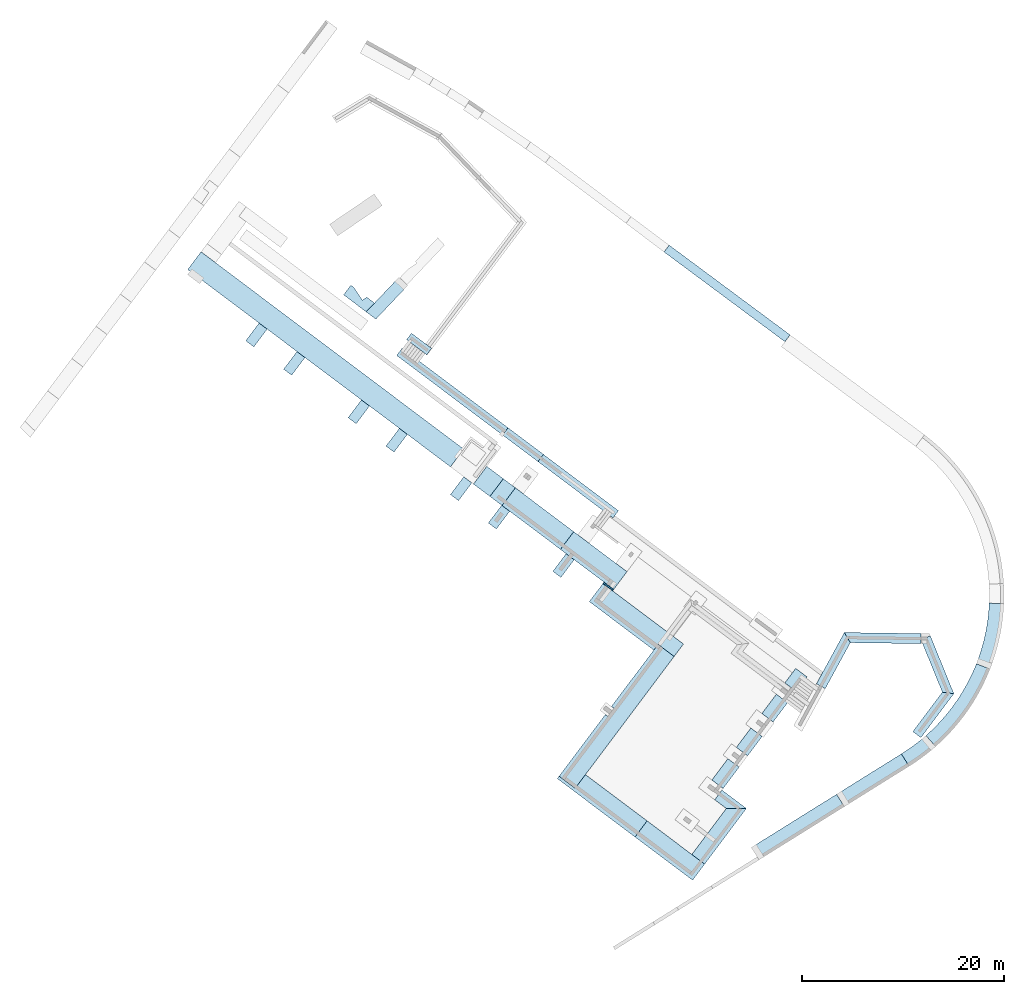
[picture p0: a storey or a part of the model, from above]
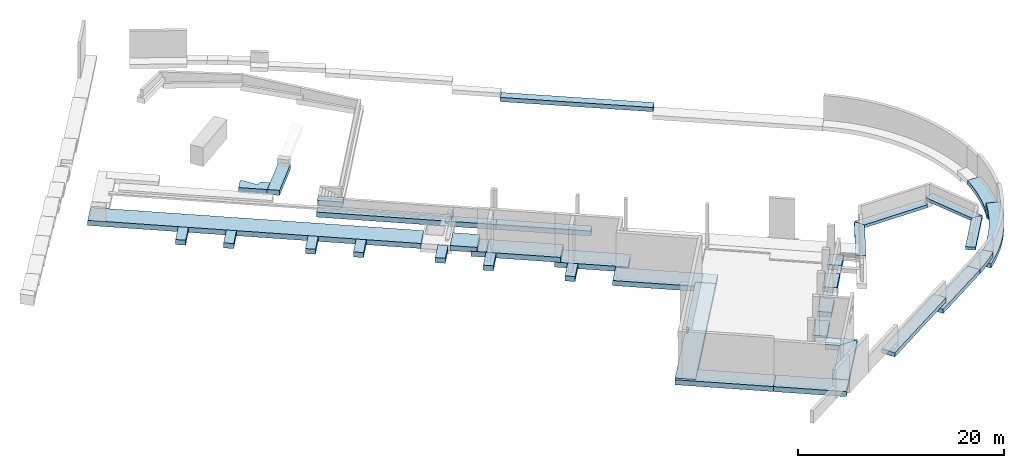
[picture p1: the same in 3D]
Properties of the parts of a building model (IFC2X3), part 1 of 3

# File
Description: ViewDefinition [CoordinationView_V2.0], RevitIdentifiers [VersionGUID: 9e385aeb-7092-4122-8eb9-5f535664c377, NumberOfSaves: 59], CoordinateReference [CoordinateBase: Coordenadas compartidas, ProjectSite: Interna]
File name: 0001
Time: 2024-03-04T15:58:39
Written by: ODA IFC SDK 22.8
Made in: 22.1.50.17 - Exporter 22.6.2.0 - IU alternativa 22.6.2.0

# IfcProject, 0001
LongName: TÍTOL DEL PROJECTE; Phase: Estado de proyecto

# IfcSite, Default
RefLatitude: 40, 24, 0, 5493; RefLongitude: -3, -40, -59, -880065; RefElevation: 0 m

# IfcBuilding
Pset_BuildingCommon - NumberOfStoreys: 4

# IfcBuildingStorey: Nivel:A- Nivell (4)
Name | LongName | Elevation (m)
PS1- Gimnàs | PS1- Gimnàs | -5.45
PS1- Vestuari | PS1- Vestuari | -4.46
P0- Escola | P0- Escola | 0
PC- Coberta STR | PC- Coberta STR | 3.4

# IfcBeam: STR- R- Formigó- Rectangular- T1:40x45 cm (6)
Type - PredefinedType: BEAM; Material: _Formigó- T1- STR
Type - Pset_BeamCommon - IsExternal: no; LoadBearing: yes
Pset_BeamCommon - Slope: 0 deg; Reference: 40x45 cm
Pset_QuantityTakeOff - Reference: 40x45 cm; sets with these values: 2
Name (STR- R- Formigó- Rectangular- T1:40x45 cm:...) | In | Span (m)
41830 | PS1- Vestuari | 2.14
41832 | PS1- Vestuari | 1.68
41862 | PS1- Gimnàs | 2.86
41888 | PS1- Gimnàs | 2.275
41890 | PS1- Vestuari | 0.88
42095 | PS1- Gimnàs | 2.96

# IfcBeam: STR- R- Formigó- Rectangular- T1:40x60 cm (11)
Type - PredefinedType: BEAM; Material: _Formigó- T1- STR
Type - Pset_BeamCommon - IsExternal: no; LoadBearing: yes
Pset_BeamCommon - Slope: 0 deg; Reference: 40x60 cm
Pset_QuantityTakeOff - Reference: 40x60 cm; sets with these values: 2
Name (STR- R- Formigó- Rectangular- T1:40x60 cm:...) | In | Span (m) | Material
41761 | P0- Escola | 58.775
41763 | P0- Escola | 14.275 | _Formigó- T1- STR, _Formigó Pobre- T1- STR
41765 | P0- Escola | 14.275 | _Formigó- T1- STR, _Formigó Pobre- T1- STR
41767 | P0- Escola | 14.275 | _Formigó- T1- STR, _Formigó Pobre- T1- STR
41772 | P0- Escola | 14.527 | _Formigó- T1- STR, _Formigó Pobre- T1- STR
41778 | P0- Escola | 14.527 | _Formigó- T1- STR, _Formigó Pobre- T1- STR
41784 | P0- Escola | 14.527 | _Formigó- T1- STR, _Formigó Pobre- T1- STR
41790 | P0- Escola | 14.527 | _Formigó- T1- STR, _Formigó Pobre- T1- STR
41796 | P0- Escola | 14.527 | _Formigó- T1- STR, _Formigó Pobre- T1- STR
41834 | PS1- Vestuari | 0.6
41860 | PS1- Gimnàs | 3.539

# IfcBeam: STR- V- Acer- FL - Platina- T1:FL 10x190 (2)
In: P0- Escola
Type - Pset_BeamCommon - IsExternal: no; LoadBearing: yes
Material: _Acer- STR; Group: Grupo de modelo:Conjunt Pergola pati infantil:42531
Pset_BeamCommon - Slope: 0 deg; Reference: FL 10x190; Span: 1.3 m
Pset_QuantityTakeOff - Reference: FL 10x190; sets with these values: 2
Name (STR- V- Acer- FL - Platina- T1:FL 10x190:...)
43241
43243

# IfcBeam: STR- V- Acer- FL - Platina- T1:FL 10x200 (3)
In: P0- Escola
Type - Pset_BeamCommon - IsExternal: no; LoadBearing: yes
Material: _Acer- STR
Pset_BeamCommon - Slope: 0 deg; Reference: FL 10x200
Pset_QuantityTakeOff - Reference: FL 10x200; sets with these values: 2
Name (STR- V- Acer- FL - Platina- T1:FL 10x200:...) | Span (m) | Group
43237 | 1.3 | Grupo de modelo:Conjunt Pergola pati infantil:42531
43239 | 1.3 | Grupo de modelo:Conjunt Pergola pati infantil:42531
98464 | 5.349

# IfcBeam: STR- V- Acer- FL - Platina- T1:FL 10x400, STR- V- Acer- FL - Platina- T1:FL 10x400:98261
In: P0- Escola
Type - Pset_BeamCommon - IsExternal: no; LoadBearing: yes
Material: _Acer- STR
Pset_BeamCommon - Slope: 0 deg; Reference: FL 10x400; Span: 1.486 m
Pset_QuantityTakeOff - Reference: FL 10x400; sets with these values: 2

# IfcBeam: STR- V- Acer- FL - Platina- T1:FL 10x80 (4)
In: P0- Escola
Type - Pset_BeamCommon - IsExternal: no; LoadBearing: yes
Material: _Acer- STR
Pset_BeamCommon - Slope: 0 deg; Reference: FL 10x80
Pset_QuantityTakeOff - Reference: FL 10x80; sets with these values: 2
Name (STR- V- Acer- FL - Platina- T1:FL 10x80:...) | Span (m)
104013 | 6.208
104717 | 5.345
105014 | 4.76
105016 | 5.345

# IfcBeam: STR- V- Acer- RHS- Rectangular- T1:120x40RHS - (576)
In: PC- Coberta STR
Type - Pset_BeamCommon - IsExternal: no; LoadBearing: yes
Material: _Acer- STR
Pset_BeamCommon - Slope: 0 deg; Reference: 120x40RHS -
Pset_QuantityTakeOff - Reference: 120x40RHS -; sets with these values: 2
Name (STR- V- Acer- RHS- Rectangular- T1:120x40RHS -:...) | Span (m) | Group
176775 | 1.94 | Grupo de modelo:Grupo de matriz 6:196769
177084 | 2.195 | Grupo de modelo:Grupo de matriz 3:177522
177525 | 2.195 | Grupo de modelo:Grupo de matriz 3:177527
177549 | 2.195 | Grupo de modelo:Grupo de matriz 3:177551
177553 | 2.195 | Grupo de modelo:Grupo de matriz 3:177555
177557 | 2.195 | Grupo de modelo:Grupo de matriz 3:177559
177561 | 2.195 | Grupo de modelo:Grupo de matriz 3:177563
177565 | 2.195 | Grupo de modelo:Grupo de matriz 3:177567
177569 | 2.195 | Grupo de modelo:Grupo de matriz 3:177571
177573 | 2.195 | Grupo de modelo:Grupo de matriz 3:177575
177577 | 2.195 | Grupo de modelo:Grupo de matriz 3:177579
177581 | 2.195 | Grupo de modelo:Grupo de matriz 3:177583
177585 | 2.195 | Grupo de modelo:Grupo de matriz 3:177587
177589 | 2.195 | Grupo de modelo:Grupo de matriz 3:177591
177593 | 2.195 | Grupo de modelo:Grupo de matriz 3:177595
177597 | 2.195 | Grupo de modelo:Grupo de matriz 3:177599
177657 | 2.195 | Grupo de modelo:Grupo de matriz 3:177659
177673 | 2.195 | Grupo de modelo:Grupo de matriz 3:177675
177676 | 2.195 | Grupo de modelo:Grupo de matriz 3:177678
177683 | 2.195 | Grupo de modelo:Grupo de matriz 3:177685
177686 | 2.195 | Grupo de modelo:Grupo de matriz 3:177688
177689 | 2.195 | Grupo de modelo:Grupo de matriz 3:177691
177692 | 2.195 | Grupo de modelo:Grupo de matriz 3:177694
177695 | 2.195 | Grupo de modelo:Grupo de matriz 3:177697
177698 | 2.195 | Grupo de modelo:Grupo de matriz 3:177700
177701 | 2.195 | Grupo de modelo:Grupo de matriz 3:177703
177704 | 2.195 | Grupo de modelo:Grupo de matriz 3:177706
177707 | 2.195 | Grupo de modelo:Grupo de matriz 3:177709
177710 | 2.195 | Grupo de modelo:Grupo de matriz 3:177712
177713 | 2.195 | Grupo de modelo:Grupo de matriz 3:177715
177716 | 2.195 | Grupo de modelo:Grupo de matriz 3:177718
177719 | 2.195 | Grupo de modelo:Grupo de matriz 3:177721
177722 | 2.195 | Grupo de modelo:Grupo de matriz 3:177724
178431 | 1.94 | Grupo de modelo:Grupo de matriz 5:187539
181486 | 2.195 | Grupo de modelo:Grupo de matriz 3:181538
181539 | 2.195 | Grupo de modelo:Grupo de matriz 3:181541
181546 | 2.195 | Grupo de modelo:Grupo de matriz 3:181548
181549 | 2.195 | Grupo de modelo:Grupo de matriz 3:181551
181552 | 2.195 | Grupo de modelo:Grupo de matriz 3:181554
181555 | 2.195 | Grupo de modelo:Grupo de matriz 3:181557
181558 | 2.195 | Grupo de modelo:Grupo de matriz 3:181560
181561 | 2.195 | Grupo de modelo:Grupo de matriz 3:181563
181564 | 2.195 | Grupo de modelo:Grupo de matriz 3:181566
181567 | 2.195 | Grupo de modelo:Grupo de matriz 3:181569
181570 | 2.195 | Grupo de modelo:Grupo de matriz 3:181572
181573 | 2.195 | Grupo de modelo:Grupo de matriz 3:181575
181576 | 2.195 | Grupo de modelo:Grupo de matriz 3:181578
181579 | 2.195 | Grupo de modelo:Grupo de matriz 3:181581
181582 | 2.195 | Grupo de modelo:Grupo de matriz 3:181584
181585 | 2.195 | Grupo de modelo:Grupo de matriz 3:181587
181589 | 2.195 | Grupo de modelo:Grupo de matriz 3:181591
181592 | 2.195 | Grupo de modelo:Grupo de matriz 3:181594
181599 | 2.195 | Grupo de modelo:Grupo de matriz 3:181601
181602 | 2.195 | Grupo de modelo:Grupo de matriz 3:181604
181605 | 2.195 | Grupo de modelo:Grupo de matriz 3:181607
181608 | 2.195 | Grupo de modelo:Grupo de matriz 3:181610
181611 | 2.195 | Grupo de modelo:Grupo de matriz 3:181613
181614 | 2.195 | Grupo de modelo:Grupo de matriz 3:181616
181617 | 2.195 | Grupo de modelo:Grupo de matriz 3:181619
181620 | 2.195 | Grupo de modelo:Grupo de matriz 3:181622
181623 | 2.195 | Grupo de modelo:Grupo de matriz 3:181625
181626 | 2.195 | Grupo de modelo:Grupo de matriz 3:181628
181629 | 2.195 | Grupo de modelo:Grupo de matriz 3:181631
181632 | 2.195 | Grupo de modelo:Grupo de matriz 3:181634
181635 | 2.195 | Grupo de modelo:Grupo de matriz 3:181637
181638 | 2.195 | Grupo de modelo:Grupo de matriz 3:181640
181968 | 2.195 | Grupo de modelo:Grupo de matriz 3:182020
182021 | 2.195 | Grupo de modelo:Grupo de matriz 3:182023
182028 | 2.195 | Grupo de modelo:Grupo de matriz 3:182030
182031 | 2.195 | Grupo de modelo:Grupo de matriz 3:182033
182034 | 2.195 | Grupo de modelo:Grupo de matriz 3:182036
182037 | 2.195 | Grupo de modelo:Grupo de matriz 3:182039
182040 | 2.195 | Grupo de modelo:Grupo de matriz 3:182042
182043 | 2.195 | Grupo de modelo:Grupo de matriz 3:182045
182046 | 2.195 | Grupo de modelo:Grupo de matriz 3:182048
182049 | 2.195 | Grupo de modelo:Grupo de matriz 3:182051
182052 | 2.195 | Grupo de modelo:Grupo de matriz 3:182054
182055 | 2.195 | Grupo de modelo:Grupo de matriz 3:182057
182058 | 2.195 | Grupo de modelo:Grupo de matriz 3:182060
182061 | 2.195 | Grupo de modelo:Grupo de matriz 3:182063
182064 | 2.195 | Grupo de modelo:Grupo de matriz 3:182066
182067 | 2.195 | Grupo de modelo:Grupo de matriz 3:182069
182071 | 2.195 | Grupo de modelo:Grupo de matriz 3:182073
182074 | 2.195 | Grupo de modelo:Grupo de matriz 3:182076
182081 | 2.195 | Grupo de modelo:Grupo de matriz 3:182083
182084 | 2.195 | Grupo de modelo:Grupo de matriz 3:182086
182087 | 2.195 | Grupo de modelo:Grupo de matriz 3:182089
182090 | 2.195 | Grupo de modelo:Grupo de matriz 3:182092
182093 | 2.195 | Grupo de modelo:Grupo de matriz 3:182095
182096 | 2.195 | Grupo de modelo:Grupo de matriz 3:182098
182099 | 2.195 | Grupo de modelo:Grupo de matriz 3:182101
182102 | 2.195 | Grupo de modelo:Grupo de matriz 3:182104
182105 | 2.195 | Grupo de modelo:Grupo de matriz 3:182107
182108 | 2.195 | Grupo de modelo:Grupo de matriz 3:182110
182111 | 2.195 | Grupo de modelo:Grupo de matriz 3:182113
182114 | 2.195 | Grupo de modelo:Grupo de matriz 3:182116
182117 | 2.195 | Grupo de modelo:Grupo de matriz 3:182119
182120 | 2.195 | Grupo de modelo:Grupo de matriz 3:182122
182450 | 2.195 | Grupo de modelo:Grupo de matriz 3:182502
182503 | 2.195 | Grupo de modelo:Grupo de matriz 3:182505
182510 | 2.195 | Grupo de modelo:Grupo de matriz 3:182512
182513 | 2.195 | Grupo de modelo:Grupo de matriz 3:182515
182516 | 2.195 | Grupo de modelo:Grupo de matriz 3:182518
182519 | 2.195 | Grupo de modelo:Grupo de matriz 3:182521
182522 | 2.195 | Grupo de modelo:Grupo de matriz 3:182524
182525 | 2.195 | Grupo de modelo:Grupo de matriz 3:182527
182528 | 2.195 | Grupo de modelo:Grupo de matriz 3:182530
182531 | 2.195 | Grupo de modelo:Grupo de matriz 3:182533
182534 | 2.195 | Grupo de modelo:Grupo de matriz 3:182536
182537 | 2.195 | Grupo de modelo:Grupo de matriz 3:182539
182540 | 2.195 | Grupo de modelo:Grupo de matriz 3:182542
182543 | 2.195 | Grupo de modelo:Grupo de matriz 3:182545
182546 | 2.195 | Grupo de modelo:Grupo de matriz 3:182548
182549 | 2.195 | Grupo de modelo:Grupo de matriz 3:182551
182553 | 2.195 | Grupo de modelo:Grupo de matriz 3:182555
182556 | 2.195 | Grupo de modelo:Grupo de matriz 3:182558
182563 | 2.195 | Grupo de modelo:Grupo de matriz 3:182565
182566 | 2.195 | Grupo de modelo:Grupo de matriz 3:182568
182569 | 2.195 | Grupo de modelo:Grupo de matriz 3:182571
182572 | 2.195 | Grupo de modelo:Grupo de matriz 3:182574
182575 | 2.195 | Grupo de modelo:Grupo de matriz 3:182577
182578 | 2.195 | Grupo de modelo:Grupo de matriz 3:182580
182581 | 2.195 | Grupo de modelo:Grupo de matriz 3:182583
182584 | 2.195 | Grupo de modelo:Grupo de matriz 3:182586
182587 | 2.195 | Grupo de modelo:Grupo de matriz 3:182589
182590 | 2.195 | Grupo de modelo:Grupo de matriz 3:182592
182593 | 2.195 | Grupo de modelo:Grupo de matriz 3:182595
182596 | 2.195 | Grupo de modelo:Grupo de matriz 3:182598
182599 | 2.195 | Grupo de modelo:Grupo de matriz 3:182601
182602 | 2.195 | Grupo de modelo:Grupo de matriz 3:182604
187542 | 1.94 | Grupo de modelo:Grupo de matriz 5:187544
187568 | 1.94 | Grupo de modelo:Grupo de matriz 5:187570
187572 | 1.94 | Grupo de modelo:Grupo de matriz 5:187574
187576 | 1.94 | Grupo de modelo:Grupo de matriz 5:187578
187580 | 1.94 | Grupo de modelo:Grupo de matriz 5:187582
187584 | 1.94 | Grupo de modelo:Grupo de matriz 5:187586
187588 | 1.94 | Grupo de modelo:Grupo de matriz 5:187590
187592 | 1.94 | Grupo de modelo:Grupo de matriz 5:187594
187596 | 1.94 | Grupo de modelo:Grupo de matriz 5:187598
187600 | 1.94 | Grupo de modelo:Grupo de matriz 5:187602
187604 | 1.94 | Grupo de modelo:Grupo de matriz 5:187606
187608 | 1.94 | Grupo de modelo:Grupo de matriz 5:187610
187612 | 1.94 | Grupo de modelo:Grupo de matriz 5:187614
187616 | 1.94 | Grupo de modelo:Grupo de matriz 5:187618
187677 | 1.94 | Grupo de modelo:Grupo de matriz 5:187679
190967 | 2.195 | Grupo de modelo:Grupo de matriz 3:190969
190970 | 2.195 | Grupo de modelo:Grupo de matriz 3:190972
190977 | 2.195 | Grupo de modelo:Grupo de matriz 3:190979
190980 | 2.195 | Grupo de modelo:Grupo de matriz 3:190982
190983 | 2.195 | Grupo de modelo:Grupo de matriz 3:190985
190986 | 2.195 | Grupo de modelo:Grupo de matriz 3:190988
190989 | 2.195 | Grupo de modelo:Grupo de matriz 3:190991
190992 | 2.195 | Grupo de modelo:Grupo de matriz 3:190994
190995 | 2.195 | Grupo de modelo:Grupo de matriz 3:190997
190998 | 2.195 | Grupo de modelo:Grupo de matriz 3:191000
191001 | 2.195 | Grupo de modelo:Grupo de matriz 3:191003
191004 | 2.195 | Grupo de modelo:Grupo de matriz 3:191006
191007 | 2.195 | Grupo de modelo:Grupo de matriz 3:191009
191010 | 2.195 | Grupo de modelo:Grupo de matriz 3:191012
191013 | 2.195 | Grupo de modelo:Grupo de matriz 3:191015
191016 | 2.195 | Grupo de modelo:Grupo de matriz 3:191018
191020 | 2.195 | Grupo de modelo:Grupo de matriz 3:191022
191023 | 2.195 | Grupo de modelo:Grupo de matriz 3:191025
191030 | 2.195 | Grupo de modelo:Grupo de matriz 3:191032
191033 | 2.195 | Grupo de modelo:Grupo de matriz 3:191035
191036 | 2.195 | Grupo de modelo:Grupo de matriz 3:191038
191039 | 2.195 | Grupo de modelo:Grupo de matriz 3:191041
191042 | 2.195 | Grupo de modelo:Grupo de matriz 3:191044
191045 | 2.195 | Grupo de modelo:Grupo de matriz 3:191047
191048 | 2.195 | Grupo de modelo:Grupo de matriz 3:191050
191051 | 2.195 | Grupo de modelo:Grupo de matriz 3:191053
191054 | 2.195 | Grupo de modelo:Grupo de matriz 3:191056
191057 | 2.195 | Grupo de modelo:Grupo de matriz 3:191059
191060 | 2.195 | Grupo de modelo:Grupo de matriz 3:191062
191063 | 2.195 | Grupo de modelo:Grupo de matriz 3:191065
191066 | 2.195 | Grupo de modelo:Grupo de matriz 3:191068
191069 | 2.195 | Grupo de modelo:Grupo de matriz 3:191071
191073 | 2.195 | Grupo de modelo:Grupo de matriz 3:191075
191076 | 2.195 | Grupo de modelo:Grupo de matriz 3:191078
191083 | 2.195 | Grupo de modelo:Grupo de matriz 3:191085
191086 | 2.195 | Grupo de modelo:Grupo de matriz 3:191088
191089 | 2.195 | Grupo de modelo:Grupo de matriz 3:191091
191092 | 2.195 | Grupo de modelo:Grupo de matriz 3:191094
191095 | 2.195 | Grupo de modelo:Grupo de matriz 3:191097
191098 | 2.195 | Grupo de modelo:Grupo de matriz 3:191100
191101 | 2.195 | Grupo de modelo:Grupo de matriz 3:191103
191104 | 2.195 | Grupo de modelo:Grupo de matriz 3:191106
191107 | 2.195 | Grupo de modelo:Grupo de matriz 3:191109
191110 | 2.195 | Grupo de modelo:Grupo de matriz 3:191112
191113 | 2.195 | Grupo de modelo:Grupo de matriz 3:191115
191116 | 2.195 | Grupo de modelo:Grupo de matriz 3:191118
191119 | 2.195 | Grupo de modelo:Grupo de matriz 3:191121
191122 | 2.195 | Grupo de modelo:Grupo de matriz 3:191124
191126 | 2.195 | Grupo de modelo:Grupo de matriz 3:191128
191129 | 2.195 | Grupo de modelo:Grupo de matriz 3:191131
191136 | 2.195 | Grupo de modelo:Grupo de matriz 3:191138
191139 | 2.195 | Grupo de modelo:Grupo de matriz 3:191141
191142 | 2.195 | Grupo de modelo:Grupo de matriz 3:191144
191145 | 2.195 | Grupo de modelo:Grupo de matriz 3:191147
191148 | 2.195 | Grupo de modelo:Grupo de matriz 3:191150
191151 | 2.195 | Grupo de modelo:Grupo de matriz 3:191153
191154 | 2.195 | Grupo de modelo:Grupo de matriz 3:191156
191157 | 2.195 | Grupo de modelo:Grupo de matriz 3:191159
191160 | 2.195 | Grupo de modelo:Grupo de matriz 3:191162
191163 | 2.195 | Grupo de modelo:Grupo de matriz 3:191165
191166 | 2.195 | Grupo de modelo:Grupo de matriz 3:191168
191169 | 2.195 | Grupo de modelo:Grupo de matriz 3:191171
191172 | 2.195 | Grupo de modelo:Grupo de matriz 3:191174
191175 | 2.195 | Grupo de modelo:Grupo de matriz 3:191177
191179 | 2.195 | Grupo de modelo:Grupo de matriz 3:191181
191182 | 2.195 | Grupo de modelo:Grupo de matriz 3:191184
191189 | 2.195 | Grupo de modelo:Grupo de matriz 3:191191
191192 | 2.195 | Grupo de modelo:Grupo de matriz 3:191194
191195 | 2.195 | Grupo de modelo:Grupo de matriz 3:191197
191198 | 2.195 | Grupo de modelo:Grupo de matriz 3:191200
191201 | 2.195 | Grupo de modelo:Grupo de matriz 3:191203
191204 | 2.195 | Grupo de modelo:Grupo de matriz 3:191206
191207 | 2.195 | Grupo de modelo:Grupo de matriz 3:191209
191210 | 2.195 | Grupo de modelo:Grupo de matriz 3:191212
191213 | 2.195 | Grupo de modelo:Grupo de matriz 3:191215
191216 | 2.195 | Grupo de modelo:Grupo de matriz 3:191218
191219 | 2.195 | Grupo de modelo:Grupo de matriz 3:191221
191222 | 2.195 | Grupo de modelo:Grupo de matriz 3:191224
191225 | 2.195 | Grupo de modelo:Grupo de matriz 3:191227
191228 | 2.195 | Grupo de modelo:Grupo de matriz 3:191230
194025 | 1.94 | Grupo de modelo:Grupo de matriz 5:194027
194028 | 1.94 | Grupo de modelo:Grupo de matriz 5:194030
194035 | 1.94 | Grupo de modelo:Grupo de matriz 5:194037
194038 | 1.94 | Grupo de modelo:Grupo de matriz 5:194040
194041 | 1.94 | Grupo de modelo:Grupo de matriz 5:194043
194044 | 1.94 | Grupo de modelo:Grupo de matriz 5:194046
194047 | 1.94 | Grupo de modelo:Grupo de matriz 5:194049
194050 | 1.94 | Grupo de modelo:Grupo de matriz 5:194052
194053 | 1.94 | Grupo de modelo:Grupo de matriz 5:194055
194056 | 1.94 | Grupo de modelo:Grupo de matriz 5:194058
194059 | 1.94 | Grupo de modelo:Grupo de matriz 5:194061
194062 | 1.94 | Grupo de modelo:Grupo de matriz 5:194064
194065 | 1.94 | Grupo de modelo:Grupo de matriz 5:194067
194068 | 1.94 | Grupo de modelo:Grupo de matriz 5:194070
194071 | 1.94 | Grupo de modelo:Grupo de matriz 5:194073
194074 | 1.94 | Grupo de modelo:Grupo de matriz 5:194076
194077 | 2.195 | Grupo de modelo:Grupo de matriz 3:194079
194080 | 2.195 | Grupo de modelo:Grupo de matriz 3:194082
194087 | 2.195 | Grupo de modelo:Grupo de matriz 3:194089
194090 | 2.195 | Grupo de modelo:Grupo de matriz 3:194092
194093 | 2.195 | Grupo de modelo:Grupo de matriz 3:194095
194096 | 2.195 | Grupo de modelo:Grupo de matriz 3:194098
194099 | 2.195 | Grupo de modelo:Grupo de matriz 3:194101
194102 | 2.195 | Grupo de modelo:Grupo de matriz 3:194104
194105 | 2.195 | Grupo de modelo:Grupo de matriz 3:194107
194108 | 2.195 | Grupo de modelo:Grupo de matriz 3:194110
194111 | 2.195 | Grupo de modelo:Grupo de matriz 3:194113
194114 | 2.195 | Grupo de modelo:Grupo de matriz 3:194116
194117 | 2.195 | Grupo de modelo:Grupo de matriz 3:194119
194120 | 2.195 | Grupo de modelo:Grupo de matriz 3:194122
194123 | 2.195 | Grupo de modelo:Grupo de matriz 3:194125
194126 | 2.195 | Grupo de modelo:Grupo de matriz 3:194128
194130 | 2.195 | Grupo de modelo:Grupo de matriz 3:194132
194133 | 2.195 | Grupo de modelo:Grupo de matriz 3:194135
194140 | 2.195 | Grupo de modelo:Grupo de matriz 3:194142
194143 | 2.195 | Grupo de modelo:Grupo de matriz 3:194145
194146 | 2.195 | Grupo de modelo:Grupo de matriz 3:194148
194149 | 2.195 | Grupo de modelo:Grupo de matriz 3:194151
194152 | 2.195 | Grupo de modelo:Grupo de matriz 3:194154
194155 | 2.195 | Grupo de modelo:Grupo de matriz 3:194157
194158 | 2.195 | Grupo de modelo:Grupo de matriz 3:194160
194161 | 2.195 | Grupo de modelo:Grupo de matriz 3:194163
194164 | 2.195 | Grupo de modelo:Grupo de matriz 3:194166
194167 | 2.195 | Grupo de modelo:Grupo de matriz 3:194169
194170 | 2.195 | Grupo de modelo:Grupo de matriz 3:194172
194173 | 2.195 | Grupo de modelo:Grupo de matriz 3:194175
194176 | 2.195 | Grupo de modelo:Grupo de matriz 3:194178
194179 | 2.195 | Grupo de modelo:Grupo de matriz 3:194181
194183 | 2.195 | Grupo de modelo:Grupo de matriz 3:194185
194186 | 2.195 | Grupo de modelo:Grupo de matriz 3:194188
194193 | 2.195 | Grupo de modelo:Grupo de matriz 3:194195
194196 | 2.195 | Grupo de modelo:Grupo de matriz 3:194198
194199 | 2.195 | Grupo de modelo:Grupo de matriz 3:194201
194202 | 2.195 | Grupo de modelo:Grupo de matriz 3:194204
194205 | 2.195 | Grupo de modelo:Grupo de matriz 3:194207
194208 | 2.195 | Grupo de modelo:Grupo de matriz 3:194210
194211 | 2.195 | Grupo de modelo:Grupo de matriz 3:194213
194214 | 2.195 | Grupo de modelo:Grupo de matriz 3:194216
194217 | 2.195 | Grupo de modelo:Grupo de matriz 3:194219
194220 | 2.195 | Grupo de modelo:Grupo de matriz 3:194222
194223 | 2.195 | Grupo de modelo:Grupo de matriz 3:194225
194226 | 2.195 | Grupo de modelo:Grupo de matriz 3:194228
194229 | 2.195 | Grupo de modelo:Grupo de matriz 3:194231
194232 | 2.195 | Grupo de modelo:Grupo de matriz 3:194234
194236 | 2.195 | Grupo de modelo:Grupo de matriz 3:194238
194239 | 2.195 | Grupo de modelo:Grupo de matriz 3:194241
194246 | 2.195 | Grupo de modelo:Grupo de matriz 3:194248
194249 | 2.195 | Grupo de modelo:Grupo de matriz 3:194251
194252 | 2.195 | Grupo de modelo:Grupo de matriz 3:194254
194255 | 2.195 | Grupo de modelo:Grupo de matriz 3:194257
194258 | 2.195 | Grupo de modelo:Grupo de matriz 3:194260
194261 | 2.195 | Grupo de modelo:Grupo de matriz 3:194263
194264 | 2.195 | Grupo de modelo:Grupo de matriz 3:194266
194267 | 2.195 | Grupo de modelo:Grupo de matriz 3:194269
194270 | 2.195 | Grupo de modelo:Grupo de matriz 3:194272
194273 | 2.195 | Grupo de modelo:Grupo de matriz 3:194275
194276 | 2.195 | Grupo de modelo:Grupo de matriz 3:194278
194279 | 2.195 | Grupo de modelo:Grupo de matriz 3:194281
194282 | 2.195 | Grupo de modelo:Grupo de matriz 3:194284
194285 | 2.195 | Grupo de modelo:Grupo de matriz 3:194287
194289 | 2.195 | Grupo de modelo:Grupo de matriz 3:194291
194292 | 2.195 | Grupo de modelo:Grupo de matriz 3:194294
194299 | 2.195 | Grupo de modelo:Grupo de matriz 3:194301
194302 | 2.195 | Grupo de modelo:Grupo de matriz 3:194304
194305 | 2.195 | Grupo de modelo:Grupo de matriz 3:194307
194308 | 2.195 | Grupo de modelo:Grupo de matriz 3:194310
194311 | 2.195 | Grupo de modelo:Grupo de matriz 3:194313
194314 | 2.195 | Grupo de modelo:Grupo de matriz 3:194316
194317 | 2.195 | Grupo de modelo:Grupo de matriz 3:194319
194320 | 2.195 | Grupo de modelo:Grupo de matriz 3:194322
194323 | 2.195 | Grupo de modelo:Grupo de matriz 3:194325
194326 | 2.195 | Grupo de modelo:Grupo de matriz 3:194328
194329 | 2.195 | Grupo de modelo:Grupo de matriz 3:194331
194332 | 2.195 | Grupo de modelo:Grupo de matriz 3:194334
194335 | 2.195 | Grupo de modelo:Grupo de matriz 3:194337
194338 | 2.195 | Grupo de modelo:Grupo de matriz 3:194340
194344 | 1.94 | Grupo de modelo:Grupo de matriz 5:194346
194347 | 1.94 | Grupo de modelo:Grupo de matriz 5:194349
194354 | 1.94 | Grupo de modelo:Grupo de matriz 5:194356
194357 | 1.94 | Grupo de modelo:Grupo de matriz 5:194359
194360 | 1.94 | Grupo de modelo:Grupo de matriz 5:194362
194363 | 1.94 | Grupo de modelo:Grupo de matriz 5:194365
194366 | 1.94 | Grupo de modelo:Grupo de matriz 5:194368
194369 | 1.94 | Grupo de modelo:Grupo de matriz 5:194371
194372 | 1.94 | Grupo de modelo:Grupo de matriz 5:194374
194375 | 1.94 | Grupo de modelo:Grupo de matriz 5:194377
194378 | 1.94 | Grupo de modelo:Grupo de matriz 5:194380
194381 | 1.94 | Grupo de modelo:Grupo de matriz 5:194383
194384 | 1.94 | Grupo de modelo:Grupo de matriz 5:194386
194387 | 1.94 | Grupo de modelo:Grupo de matriz 5:194389
194390 | 1.94 | Grupo de modelo:Grupo de matriz 5:194392
194393 | 1.94 | Grupo de modelo:Grupo de matriz 5:194395
194396 | 2.195 | Grupo de modelo:Grupo de matriz 3:194398
194399 | 2.195 | Grupo de modelo:Grupo de matriz 3:194401
194406 | 2.195 | Grupo de modelo:Grupo de matriz 3:194408
194409 | 2.195 | Grupo de modelo:Grupo de matriz 3:194411
194412 | 2.195 | Grupo de modelo:Grupo de matriz 3:194414
194415 | 2.195 | Grupo de modelo:Grupo de matriz 3:194417
194418 | 2.195 | Grupo de modelo:Grupo de matriz 3:194420
194421 | 2.195 | Grupo de modelo:Grupo de matriz 3:194423
194424 | 2.195 | Grupo de modelo:Grupo de matriz 3:194426
194427 | 2.195 | Grupo de modelo:Grupo de matriz 3:194429
194430 | 2.195 | Grupo de modelo:Grupo de matriz 3:194432
194433 | 2.195 | Grupo de modelo:Grupo de matriz 3:194435
194436 | 2.195 | Grupo de modelo:Grupo de matriz 3:194438
194439 | 2.195 | Grupo de modelo:Grupo de matriz 3:194441
194442 | 2.195 | Grupo de modelo:Grupo de matriz 3:194444
194445 | 2.195 | Grupo de modelo:Grupo de matriz 3:194447
194449 | 2.195 | Grupo de modelo:Grupo de matriz 3:194451
194452 | 2.195 | Grupo de modelo:Grupo de matriz 3:194454
194459 | 2.195 | Grupo de modelo:Grupo de matriz 3:194461
194462 | 2.195 | Grupo de modelo:Grupo de matriz 3:194464
194465 | 2.195 | Grupo de modelo:Grupo de matriz 3:194467
194468 | 2.195 | Grupo de modelo:Grupo de matriz 3:194470
194471 | 2.195 | Grupo de modelo:Grupo de matriz 3:194473
194474 | 2.195 | Grupo de modelo:Grupo de matriz 3:194476
194477 | 2.195 | Grupo de modelo:Grupo de matriz 3:194479
194480 | 2.195 | Grupo de modelo:Grupo de matriz 3:194482
194483 | 2.195 | Grupo de modelo:Grupo de matriz 3:194485
194486 | 2.195 | Grupo de modelo:Grupo de matriz 3:194488
194489 | 2.195 | Grupo de modelo:Grupo de matriz 3:194491
194492 | 2.195 | Grupo de modelo:Grupo de matriz 3:194494
194495 | 2.195 | Grupo de modelo:Grupo de matriz 3:194497
194498 | 2.195 | Grupo de modelo:Grupo de matriz 3:194500
194502 | 2.195 | Grupo de modelo:Grupo de matriz 3:194504
194505 | 2.195 | Grupo de modelo:Grupo de matriz 3:194507
194512 | 2.195 | Grupo de modelo:Grupo de matriz 3:194514
194515 | 2.195 | Grupo de modelo:Grupo de matriz 3:194517
194518 | 2.195 | Grupo de modelo:Grupo de matriz 3:194520
194521 | 2.195 | Grupo de modelo:Grupo de matriz 3:194523
194524 | 2.195 | Grupo de modelo:Grupo de matriz 3:194526
194527 | 2.195 | Grupo de modelo:Grupo de matriz 3:194529
194530 | 2.195 | Grupo de modelo:Grupo de matriz 3:194532
194533 | 2.195 | Grupo de modelo:Grupo de matriz 3:194535
194536 | 2.195 | Grupo de modelo:Grupo de matriz 3:194538
194539 | 2.195 | Grupo de modelo:Grupo de matriz 3:194541
194542 | 2.195 | Grupo de modelo:Grupo de matriz 3:194544
194545 | 2.195 | Grupo de modelo:Grupo de matriz 3:194547
194548 | 2.195 | Grupo de modelo:Grupo de matriz 3:194550
194551 | 2.195 | Grupo de modelo:Grupo de matriz 3:194553
194555 | 2.195 | Grupo de modelo:Grupo de matriz 3:194557
194558 | 2.195 | Grupo de modelo:Grupo de matriz 3:194560
194565 | 2.195 | Grupo de modelo:Grupo de matriz 3:194567
194568 | 2.195 | Grupo de modelo:Grupo de matriz 3:194570
194571 | 2.195 | Grupo de modelo:Grupo de matriz 3:194573
194574 | 2.195 | Grupo de modelo:Grupo de matriz 3:194576
194577 | 2.195 | Grupo de modelo:Grupo de matriz 3:194579
194580 | 2.195 | Grupo de modelo:Grupo de matriz 3:194582
194583 | 2.195 | Grupo de modelo:Grupo de matriz 3:194585
194586 | 2.195 | Grupo de modelo:Grupo de matriz 3:194588
194589 | 2.195 | Grupo de modelo:Grupo de matriz 3:194591
194592 | 2.195 | Grupo de modelo:Grupo de matriz 3:194594
194595 | 2.195 | Grupo de modelo:Grupo de matriz 3:194597
194598 | 2.195 | Grupo de modelo:Grupo de matriz 3:194600
194601 | 2.195 | Grupo de modelo:Grupo de matriz 3:194603
194604 | 2.195 | Grupo de modelo:Grupo de matriz 3:194606
194608 | 2.195 | Grupo de modelo:Grupo de matriz 3:194610
194611 | 2.195 | Grupo de modelo:Grupo de matriz 3:194613
194618 | 2.195 | Grupo de modelo:Grupo de matriz 3:194620
194621 | 2.195 | Grupo de modelo:Grupo de matriz 3:194623
194624 | 2.195 | Grupo de modelo:Grupo de matriz 3:194626
194627 | 2.195 | Grupo de modelo:Grupo de matriz 3:194629
194630 | 2.195 | Grupo de modelo:Grupo de matriz 3:194632
194633 | 2.195 | Grupo de modelo:Grupo de matriz 3:194635
194636 | 2.195 | Grupo de modelo:Grupo de matriz 3:194638
194639 | 2.195 | Grupo de modelo:Grupo de matriz 3:194641
194642 | 2.195 | Grupo de modelo:Grupo de matriz 3:194644
194645 | 2.195 | Grupo de modelo:Grupo de matriz 3:194647
194648 | 2.195 | Grupo de modelo:Grupo de matriz 3:194650
194651 | 2.195 | Grupo de modelo:Grupo de matriz 3:194653
194654 | 2.195 | Grupo de modelo:Grupo de matriz 3:194656
194657 | 2.195 | Grupo de modelo:Grupo de matriz 3:194659
194663 | 1.94 | Grupo de modelo:Grupo de matriz 5:194665
194666 | 1.94 | Grupo de modelo:Grupo de matriz 5:194668
194673 | 1.94 | Grupo de modelo:Grupo de matriz 5:194675
194676 | 1.94 | Grupo de modelo:Grupo de matriz 5:194678
194679 | 1.94 | Grupo de modelo:Grupo de matriz 5:194681
194682 | 1.94 | Grupo de modelo:Grupo de matriz 5:194684
194685 | 1.94 | Grupo de modelo:Grupo de matriz 5:194687
194688 | 1.94 | Grupo de modelo:Grupo de matriz 5:194690
194691 | 1.94 | Grupo de modelo:Grupo de matriz 5:194693
194694 | 1.94 | Grupo de modelo:Grupo de matriz 5:194696
194697 | 1.94 | Grupo de modelo:Grupo de matriz 5:194699
194700 | 1.94 | Grupo de modelo:Grupo de matriz 5:194702
194703 | 1.94 | Grupo de modelo:Grupo de matriz 5:194705
194706 | 1.94 | Grupo de modelo:Grupo de matriz 5:194708
194709 | 1.94 | Grupo de modelo:Grupo de matriz 5:194711
194712 | 1.94 | Grupo de modelo:Grupo de matriz 5:194714
194715 | 2.195 | Grupo de modelo:Grupo de matriz 3:194717
194718 | 2.195 | Grupo de modelo:Grupo de matriz 3:194720
194725 | 2.195 | Grupo de modelo:Grupo de matriz 3:194727
194728 | 2.195 | Grupo de modelo:Grupo de matriz 3:194730
194731 | 2.195 | Grupo de modelo:Grupo de matriz 3:194733
194734 | 2.195 | Grupo de modelo:Grupo de matriz 3:194736
194737 | 2.195 | Grupo de modelo:Grupo de matriz 3:194739
194740 | 2.195 | Grupo de modelo:Grupo de matriz 3:194742
194743 | 2.195 | Grupo de modelo:Grupo de matriz 3:194745
194746 | 2.195 | Grupo de modelo:Grupo de matriz 3:194748
194749 | 2.195 | Grupo de modelo:Grupo de matriz 3:194751
194752 | 2.195 | Grupo de modelo:Grupo de matriz 3:194754
194755 | 2.195 | Grupo de modelo:Grupo de matriz 3:194757
194758 | 2.195 | Grupo de modelo:Grupo de matriz 3:194760
194761 | 2.195 | Grupo de modelo:Grupo de matriz 3:194763
194764 | 2.195 | Grupo de modelo:Grupo de matriz 3:194766
194768 | 2.195 | Grupo de modelo:Grupo de matriz 3:194770
194771 | 2.195 | Grupo de modelo:Grupo de matriz 3:194773
194778 | 2.195 | Grupo de modelo:Grupo de matriz 3:194780
194781 | 2.195 | Grupo de modelo:Grupo de matriz 3:194783
194784 | 2.195 | Grupo de modelo:Grupo de matriz 3:194786
194787 | 2.195 | Grupo de modelo:Grupo de matriz 3:194789
194790 | 2.195 | Grupo de modelo:Grupo de matriz 3:194792
194793 | 2.195 | Grupo de modelo:Grupo de matriz 3:194795
194796 | 2.195 | Grupo de modelo:Grupo de matriz 3:194798
194799 | 2.195 | Grupo de modelo:Grupo de matriz 3:194801
194802 | 2.195 | Grupo de modelo:Grupo de matriz 3:194804
194805 | 2.195 | Grupo de modelo:Grupo de matriz 3:194807
194808 | 2.195 | Grupo de modelo:Grupo de matriz 3:194810
194811 | 2.195 | Grupo de modelo:Grupo de matriz 3:194813
194814 | 2.195 | Grupo de modelo:Grupo de matriz 3:194816
194817 | 2.195 | Grupo de modelo:Grupo de matriz 3:194819
194821 | 2.195 | Grupo de modelo:Grupo de matriz 3:194823
194824 | 2.195 | Grupo de modelo:Grupo de matriz 3:194826
194831 | 2.195 | Grupo de modelo:Grupo de matriz 3:194833
194834 | 2.195 | Grupo de modelo:Grupo de matriz 3:194836
194837 | 2.195 | Grupo de modelo:Grupo de matriz 3:194839
194840 | 2.195 | Grupo de modelo:Grupo de matriz 3:194842
194843 | 2.195 | Grupo de modelo:Grupo de matriz 3:194845
194846 | 2.195 | Grupo de modelo:Grupo de matriz 3:194848
194849 | 2.195 | Grupo de modelo:Grupo de matriz 3:194851
194852 | 2.195 | Grupo de modelo:Grupo de matriz 3:194854
194855 | 2.195 | Grupo de modelo:Grupo de matriz 3:194857
194858 | 2.195 | Grupo de modelo:Grupo de matriz 3:194860
194861 | 2.195 | Grupo de modelo:Grupo de matriz 3:194863
194864 | 2.195 | Grupo de modelo:Grupo de matriz 3:194866
194867 | 2.195 | Grupo de modelo:Grupo de matriz 3:194869
194870 | 2.195 | Grupo de modelo:Grupo de matriz 3:194872
194874 | 2.195 | Grupo de modelo:Grupo de matriz 3:194876
194877 | 2.195 | Grupo de modelo:Grupo de matriz 3:194879
194884 | 2.195 | Grupo de modelo:Grupo de matriz 3:194886
194887 | 2.195 | Grupo de modelo:Grupo de matriz 3:194889
194890 | 2.195 | Grupo de modelo:Grupo de matriz 3:194892
194893 | 2.195 | Grupo de modelo:Grupo de matriz 3:194895
194896 | 2.195 | Grupo de modelo:Grupo de matriz 3:194898
194899 | 2.195 | Grupo de modelo:Grupo de matriz 3:194901
194902 | 2.195 | Grupo de modelo:Grupo de matriz 3:194904
194905 | 2.195 | Grupo de modelo:Grupo de matriz 3:194907
194908 | 2.195 | Grupo de modelo:Grupo de matriz 3:194910
194911 | 2.195 | Grupo de modelo:Grupo de matriz 3:194913
194914 | 2.195 | Grupo de modelo:Grupo de matriz 3:194916
194917 | 2.195 | Grupo de modelo:Grupo de matriz 3:194919
194920 | 2.195 | Grupo de modelo:Grupo de matriz 3:194922
194923 | 2.195 | Grupo de modelo:Grupo de matriz 3:194925
194927 | 2.195 | Grupo de modelo:Grupo de matriz 3:194929
194930 | 2.195 | Grupo de modelo:Grupo de matriz 3:194932
194937 | 2.195 | Grupo de modelo:Grupo de matriz 3:194939
194940 | 2.195 | Grupo de modelo:Grupo de matriz 3:194942
194943 | 2.195 | Grupo de modelo:Grupo de matriz 3:194945
194946 | 2.195 | Grupo de modelo:Grupo de matriz 3:194948
194949 | 2.195 | Grupo de modelo:Grupo de matriz 3:194951
194952 | 2.195 | Grupo de modelo:Grupo de matriz 3:194954
194955 | 2.195 | Grupo de modelo:Grupo de matriz 3:194957
194958 | 2.195 | Grupo de modelo:Grupo de matriz 3:194960
194961 | 2.195 | Grupo de modelo:Grupo de matriz 3:194963
194964 | 2.195 | Grupo de modelo:Grupo de matriz 3:194966
194967 | 2.195 | Grupo de modelo:Grupo de matriz 3:194969
194970 | 2.195 | Grupo de modelo:Grupo de matriz 3:194972
194973 | 2.195 | Grupo de modelo:Grupo de matriz 3:194975
194976 | 2.195 | Grupo de modelo:Grupo de matriz 3:194978
196772 | 1.94 | Grupo de modelo:Grupo de matriz 6:196774
196788 | 1.94 | Grupo de modelo:Grupo de matriz 6:196790
196792 | 1.94 | Grupo de modelo:Grupo de matriz 6:196794
196796 | 1.94 | Grupo de modelo:Grupo de matriz 6:196798
196800 | 1.94 | Grupo de modelo:Grupo de matriz 6:196802
196804 | 1.94 | Grupo de modelo:Grupo de matriz 6:196806
196808 | 1.94 | Grupo de modelo:Grupo de matriz 6:196810
196812 | 1.94 | Grupo de modelo:Grupo de matriz 6:196814
196816 | 1.94 | Grupo de modelo:Grupo de matriz 6:196818
196820 | 1.94 | Grupo de modelo:Grupo de matriz 6:196822
196824 | 1.94 | Grupo de modelo:Grupo de matriz 6:196826
196828 | 1.94 | Grupo de modelo:Grupo de matriz 6:196830
196832 | 1.94 | Grupo de modelo:Grupo de matriz 6:196834
196836 | 1.94 | Grupo de modelo:Grupo de matriz 6:196838
196896 | 1.94 | Grupo de modelo:Grupo de matriz 6:196898
197241 | 1.94 | Grupo de modelo:Grupo de matriz 6:197243
197244 | 1.94 | Grupo de modelo:Grupo de matriz 6:197246
197251 | 1.94 | Grupo de modelo:Grupo de matriz 6:197253
197254 | 1.94 | Grupo de modelo:Grupo de matriz 6:197256
197257 | 1.94 | Grupo de modelo:Grupo de matriz 6:197259
197260 | 1.94 | Grupo de modelo:Grupo de matriz 6:197262
197263 | 1.94 | Grupo de modelo:Grupo de matriz 6:197265
197266 | 1.94 | Grupo de modelo:Grupo de matriz 6:197268
197269 | 1.94 | Grupo de modelo:Grupo de matriz 6:197271
197272 | 1.94 | Grupo de modelo:Grupo de matriz 6:197274
197275 | 1.94 | Grupo de modelo:Grupo de matriz 6:197277
197278 | 1.94 | Grupo de modelo:Grupo de matriz 6:197280
197281 | 1.94 | Grupo de modelo:Grupo de matriz 6:197283
197284 | 1.94 | Grupo de modelo:Grupo de matriz 6:197286
197287 | 1.94 | Grupo de modelo:Grupo de matriz 6:197289
197290 | 1.94 | Grupo de modelo:Grupo de matriz 6:197292
197295 | 1.94 | Grupo de modelo:Grupo de matriz 6:197297
197298 | 1.94 | Grupo de modelo:Grupo de matriz 6:197300
197305 | 1.94 | Grupo de modelo:Grupo de matriz 6:197307
197308 | 1.94 | Grupo de modelo:Grupo de matriz 6:197310
197311 | 1.94 | Grupo de modelo:Grupo de matriz 6:197313
197314 | 1.94 | Grupo de modelo:Grupo de matriz 6:197316
197317 | 1.94 | Grupo de modelo:Grupo de matriz 6:197319
197320 | 1.94 | Grupo de modelo:Grupo de matriz 6:197322
197323 | 1.94 | Grupo de modelo:Grupo de matriz 6:197325
197326 | 1.94 | Grupo de modelo:Grupo de matriz 6:197328
197329 | 1.94 | Grupo de modelo:Grupo de matriz 6:197331
197332 | 1.94 | Grupo de modelo:Grupo de matriz 6:197334
197335 | 1.94 | Grupo de modelo:Grupo de matriz 6:197337
197338 | 1.94 | Grupo de modelo:Grupo de matriz 6:197340
197341 | 1.94 | Grupo de modelo:Grupo de matriz 6:197343
197344 | 1.94 | Grupo de modelo:Grupo de matriz 6:197346
197349 | 1.94 | Grupo de modelo:Grupo de matriz 6:197351
197352 | 1.94 | Grupo de modelo:Grupo de matriz 6:197354
197359 | 1.94 | Grupo de modelo:Grupo de matriz 6:197361
197362 | 1.94 | Grupo de modelo:Grupo de matriz 6:197364
197365 | 1.94 | Grupo de modelo:Grupo de matriz 6:197367
197368 | 1.94 | Grupo de modelo:Grupo de matriz 6:197370
197371 | 1.94 | Grupo de modelo:Grupo de matriz 6:197373
197374 | 1.94 | Grupo de modelo:Grupo de matriz 6:197376
197377 | 1.94 | Grupo de modelo:Grupo de matriz 6:197379
197380 | 1.94 | Grupo de modelo:Grupo de matriz 6:197382
197383 | 1.94 | Grupo de modelo:Grupo de matriz 6:197385
197386 | 1.94 | Grupo de modelo:Grupo de matriz 6:197388
197389 | 1.94 | Grupo de modelo:Grupo de matriz 6:197391
197392 | 1.94 | Grupo de modelo:Grupo de matriz 6:197394
197395 | 1.94 | Grupo de modelo:Grupo de matriz 6:197397
197398 | 1.94 | Grupo de modelo:Grupo de matriz 6:197400

# IfcBeam: STR- V- Acer- RHS- Rectangular- T1:120x60RHS (64)
Type - Pset_BeamCommon - IsExternal: no; LoadBearing: yes
Material: _Acer- STR
Pset_BeamCommon - Slope: 0 deg; Reference: 120x60RHS
Pset_QuantityTakeOff - Reference: 120x60RHS; sets with these values: 2
Name (STR- V- Acer- RHS- Rectangular- T1:120x60RHS:...) | In | Span (m) | Group
42526 | PC- Coberta STR | 3.564 | Grupo de modelo:pergola:42530
42528 | PC- Coberta STR | 3.56 | Grupo de modelo:pergola:42530
42532 | PC- Coberta STR | 3.564 | Grupo de modelo:pergola:42536
42534 | P0- Escola | 3.56 | Grupo de modelo:pergola:42536
42537 | PC- Coberta STR | 3.564 | Grupo de modelo:pergola:42541
42539 | P0- Escola | 3.56 | Grupo de modelo:pergola:42541
42542 | PC- Coberta STR | 3.564 | Grupo de modelo:pergola:42546
42544 | P0- Escola | 3.56 | Grupo de modelo:pergola:42546
42547 | PC- Coberta STR | 3.564 | Grupo de modelo:pergola:42551
42549 | P0- Escola | 3.56 | Grupo de modelo:pergola:42551
42552 | PC- Coberta STR | 3.564 | Grupo de modelo:pergola:42556
42554 | P0- Escola | 3.56 | Grupo de modelo:pergola:42556
42557 | PC- Coberta STR | 3.564 | Grupo de modelo:pergola:42561
42559 | P0- Escola | 3.56 | Grupo de modelo:pergola:42561
42562 | PC- Coberta STR | 6.85 | Grupo de modelo:Conjunt Pergola pati infantil:42531
42564 | PC- Coberta STR | 6.85 | Grupo de modelo:Conjunt Pergola pati infantil:42531
42566 | PC- Coberta STR | 6.85 | Grupo de modelo:Conjunt Pergola pati infantil:42531
42568 | PC- Coberta STR | 6.85 | Grupo de modelo:Conjunt Pergola pati infantil:42531
42570 | PC- Coberta STR | 6.85 | Grupo de modelo:Conjunt Pergola pati infantil:42531
42572 | PC- Coberta STR | 6.85 | Grupo de modelo:Conjunt Pergola pati infantil:42531
84592 | PC- Coberta STR | 16.625 | Grupo de modelo:STR- Pergola pati infantil:84624
84594 | PC- Coberta STR | 4.04 | Grupo de modelo:STR- Pergola pati infantil:84624
84596 | PC- Coberta STR | 4.04 | Grupo de modelo:STR- Pergola pati infantil:84624
84598 | PC- Coberta STR | 4.04 | Grupo de modelo:STR- Pergola pati infantil:84624
84600 | PC- Coberta STR | 4.04 | Grupo de modelo:STR- Pergola pati infantil:84624
84602 | PC- Coberta STR | 4.04 | Grupo de modelo:STR- Pergola pati infantil:84624
84604 | PC- Coberta STR | 4.04 | Grupo de modelo:STR- Pergola pati infantil:84624
84606 | PC- Coberta STR | 4.04 | Grupo de modelo:STR- Pergola pati infantil:84624
84627 | PC- Coberta STR | 4.04 | Grupo de modelo:STR- Pergola pati infantil:84624
84633 | PC- Coberta STR | 16.625 | Grupo de modelo:STR- Pergola pati infantil:84665
84635 | PC- Coberta STR | 4.04 | Grupo de modelo:STR- Pergola pati infantil:84665
84637 | PC- Coberta STR | 4.04 | Grupo de modelo:STR- Pergola pati infantil:84665
84639 | PC- Coberta STR | 4.04 | Grupo de modelo:STR- Pergola pati infantil:84665
84641 | PC- Coberta STR | 4.04 | Grupo de modelo:STR- Pergola pati infantil:84665
84643 | PC- Coberta STR | 4.04 | Grupo de modelo:STR- Pergola pati infantil:84665
84645 | PC- Coberta STR | 4.04 | Grupo de modelo:STR- Pergola pati infantil:84665
84647 | PC- Coberta STR | 4.04 | Grupo de modelo:STR- Pergola pati infantil:84665
84668 | PC- Coberta STR | 4.04 | Grupo de modelo:STR- Pergola pati infantil:84665
84674 | PC- Coberta STR | 16.625 | Grupo de modelo:STR- Pergola pati infantil:84706
84676 | PC- Coberta STR | 4.04 | Grupo de modelo:STR- Pergola pati infantil:84706
84678 | PC- Coberta STR | 4.04 | Grupo de modelo:STR- Pergola pati infantil:84706
84680 | PC- Coberta STR | 4.04 | Grupo de modelo:STR- Pergola pati infantil:84706
84682 | PC- Coberta STR | 4.04 | Grupo de modelo:STR- Pergola pati infantil:84706
84684 | PC- Coberta STR | 4.04 | Grupo de modelo:STR- Pergola pati infantil:84706
84686 | PC- Coberta STR | 4.04 | Grupo de modelo:STR- Pergola pati infantil:84706
84688 | PC- Coberta STR | 4.04 | Grupo de modelo:STR- Pergola pati infantil:84706
84709 | PC- Coberta STR | 4.04 | Grupo de modelo:STR- Pergola pati infantil:84706
84715 | PC- Coberta STR | 16.625 | Grupo de modelo:STR- Pergola pati infantil:84747
84717 | PC- Coberta STR | 4.04 | Grupo de modelo:STR- Pergola pati infantil:84747
84719 | PC- Coberta STR | 4.04 | Grupo de modelo:STR- Pergola pati infantil:84747
84721 | PC- Coberta STR | 4.04 | Grupo de modelo:STR- Pergola pati infantil:84747
84723 | PC- Coberta STR | 4.04 | Grupo de modelo:STR- Pergola pati infantil:84747
84725 | PC- Coberta STR | 4.04 | Grupo de modelo:STR- Pergola pati infantil:84747
84727 | PC- Coberta STR | 4.04 | Grupo de modelo:STR- Pergola pati infantil:84747
84729 | PC- Coberta STR | 4.04 | Grupo de modelo:STR- Pergola pati infantil:84747
84750 | PC- Coberta STR | 4.04 | Grupo de modelo:STR- Pergola pati infantil:84747
185203 | PC- Coberta STR | 4.04 | Grupo de modelo:STR- Pergola pati infantil:84747
185282 | PC- Coberta STR | 4.04 | Grupo de modelo:STR- Pergola pati infantil:84624
185285 | PC- Coberta STR | 4.04 | Grupo de modelo:STR- Pergola pati infantil:84665
185288 | PC- Coberta STR | 4.04 | Grupo de modelo:STR- Pergola pati infantil:84706
196501 | PC- Coberta STR | 4.04 | Grupo de modelo:STR- Pergola pati infantil:84747
196582 | PC- Coberta STR | 4.04 | Grupo de modelo:STR- Pergola pati infantil:84624
196585 | PC- Coberta STR | 4.04 | Grupo de modelo:STR- Pergola pati infantil:84665
196588 | PC- Coberta STR | 4.04 | Grupo de modelo:STR- Pergola pati infantil:84706

# IfcBeam: STR- V- Acer- UPE- T1:UPE 200 (4)
In: P0- Escola
Type - Pset_BeamCommon - IsExternal: no; LoadBearing: yes
Material: _Acer- STR
Pset_BeamCommon - Reference: UPE 200
Pset_QuantityTakeOff - Reference: UPE 200; sets with these values: 2
Name (STR- V- Acer- UPE- T1:UPE 200:...) | Span (m) | Slope (deg)
102110 | 3.13 | 30.3987
102134 | 3.729 | 0
103325 | 3.13 | 30.3987
103327 | 3.729 | 0

# IfcBeam: STR- V- Formigó- Rectangular- T1:30x120 cm (8)
In: PC- Coberta STR
Type - PredefinedType: BEAM; Material: _Formigó- T1- STR
Type - Pset_BeamCommon - IsExternal: no; LoadBearing: yes
Pset_BeamCommon - Slope: 0 deg; Reference: 30x120 cm
Pset_QuantityTakeOff - Reference: 30x120 cm; sets with these values: 2
Name (STR- V- Formigó- Rectangular- T1:30x120 cm:...) | Span (m) | Group
41218 | 18.425 | Grupo de modelo:STR- Jàsseres pati interior:42061
41220 | 18.56 | Grupo de modelo:STR- Jàsseres pati interior:42061
42064 | 18.425 | Grupo de modelo:STR- Jàsseres pati interior:42072
42066 | 18.423 | Grupo de modelo:STR- Jàsseres pati interior:42072
42075 | 18.425 | Grupo de modelo:STR- Jàsseres pati interior:42083
42077 | 18.423 | Grupo de modelo:STR- Jàsseres pati interior:42083
42086 | 18.425 | Grupo de modelo:STR- Jàsseres pati interior:42094
42088 | 18.423 | Grupo de modelo:STR- Jàsseres pati interior:42094

# IfcBeam: STR- V- Formigó- Rectangular- T1:30x120 cm (13)
Type - Pset_BeamCommon - IsExternal: no; LoadBearing: yes
Material: _Formigó- T1- STR
Pset_BeamCommon - Slope: 0 deg; Reference: 30x120 cm
Pset_QuantityTakeOff - Reference: 30x120 cm; sets with these values: 2
Name (STR- V- Formigó- Rectangular- T1:30x120 cm:...) | In | Span (m)
41159 | PC- Coberta STR | 24
41161 | PC- Coberta STR | 4.7 | Group: Grupo de modelo:STR- Jàsseres pati interior:42061
41163 | P0- Escola | 37.785
41185 | PC- Coberta STR | 23.56
41187 | PC- Coberta STR | 71.5
41394 | P0- Escola | 4.32
41642 | P0- Escola | 26.45
41708 | PC- Coberta STR | 33.55
41710 | PC- Coberta STR | 37.95
41809 | P0- Escola | 1.667
42062 | PC- Coberta STR | 4.7 | Group: Grupo de modelo:STR- Jàsseres pati interior:42072
42073 | PC- Coberta STR | 4.7 | Group: Grupo de modelo:STR- Jàsseres pati interior:42083
42084 | PC- Coberta STR | 4.7 | Group: Grupo de modelo:STR- Jàsseres pati interior:42094

# IfcBeam: STR- V- Formigó- Rectangular- T1:30x59 cm (4)
In: P0- Escola
Type - Pset_BeamCommon - IsExternal: no; LoadBearing: yes
Material: _Formigó- T1- STR
Pset_BeamCommon - Slope: 0 deg; Reference: 30x59 cm
Pset_QuantityTakeOff - Reference: 30x59 cm; sets with these values: 2
Name (STR- V- Formigó- Rectangular- T1:30x59 cm:...) | Span (m)
41165 | 7.871
41299 | 23.975
41387 | 10.089
41389 | 6.199

# IfcBeam: STR- V- Formigó- Rectangular- T1:30x70 cm (8)
In: P0- Escola
Type - PredefinedType: BEAM; Material: _Formigó- T1- STR
Type - Pset_BeamCommon - IsExternal: no; LoadBearing: yes
Pset_BeamCommon - Slope: 0 deg; Reference: 30x70 cm
Pset_QuantityTakeOff - Reference: 30x70 cm; sets with these values: 2
Name (STR- V- Formigó- Rectangular- T1:30x70 cm:...) | Span (m)
41240 | 5.594
41242 | 12.7
41244 | 5.594
41391 | 2.489
41442 | 3.34
41479 | 2.044
41481 | 4.55
41485 | 5.6

# IfcBeam: STR- V- Formigó- Rectangular- T1:30x80 cm, STR- V- Formigó- Rectangular- T1:30x80 cm:42092
In: PC- Coberta STR
Type - PredefinedType: BEAM; Material: _Formigó- T1- STR
Type - Pset_BeamCommon - IsExternal: no; LoadBearing: yes
Pset_BeamCommon - Slope: 0 deg; Reference: 30x80 cm; Span: 5.437 m
Pset_QuantityTakeOff - Reference: 30x80 cm; sets with these values: 2
Group: Grupo de modelo:STR- Jàsseres pati interior:42094

# IfcBeam: STR- V- Formigó- Rectangular- T1:30x80 cm (8)
In: PC- Coberta STR
Type - Pset_BeamCommon - IsExternal: no; LoadBearing: yes
Material: _Formigó- T1- STR
Pset_BeamCommon - Slope: 0 deg; Reference: 30x80 cm
Pset_QuantityTakeOff - Reference: 30x80 cm; sets with these values: 2
Name (STR- V- Formigó- Rectangular- T1:30x80 cm:...) | Span (m) | Group
41189 | 24
42057 | 5.437 | Grupo de modelo:STR- Jàsseres pati interior:42061
42059 | 5.437 | Grupo de modelo:STR- Jàsseres pati interior:42061
42068 | 5.437 | Grupo de modelo:STR- Jàsseres pati interior:42072
42070 | 5.437 | Grupo de modelo:STR- Jàsseres pati interior:42072
42079 | 5.437 | Grupo de modelo:STR- Jàsseres pati interior:42083
42081 | 5.437 | Grupo de modelo:STR- Jàsseres pati interior:42083
42090 | 5.437 | Grupo de modelo:STR- Jàsseres pati interior:42094

# IfcBeam: STR- V- Formigó- Rectangular- T1:40x120 cm (5)
In: P0- Escola
Type - PredefinedType: BEAM; Material: _Formigó- T1- STR
Type - Pset_BeamCommon - IsExternal: no; LoadBearing: yes
Pset_BeamCommon - Slope: 0 deg; Reference: 40x120 cm
Pset_QuantityTakeOff - Reference: 40x120 cm; sets with these values: 2
Name (STR- V- Formigó- Rectangular- T1:40x120 cm:...) | Span (m)
41319 | 12.455
41398 | 11.8
41402 | 11.962
41406 | 11.8
41410 | 11.8

# IfcBeam: STR- V- Formigó- Rectangular- T1:40x59 cm (5)
In: P0- Escola
Type - Pset_BeamCommon - IsExternal: no; LoadBearing: yes
Material: _Formigó- T1- STR
Pset_BeamCommon - Slope: 0 deg; Reference: 40x59 cm
Pset_QuantityTakeOff - Reference: 40x59 cm; sets with these values: 2
Name (STR- V- Formigó- Rectangular- T1:40x59 cm:...) | Span (m)
41376 | 5.989
41400 | 6.339
41404 | 6.339
41408 | 5.989
41412 | 5.786

# IfcBeam: STR- V- Formigó- Rectangular- T1:40x80 cm (2)
In: PC- Coberta STR
Type - Pset_BeamCommon - IsExternal: no; LoadBearing: yes
Material: _Formigó- T1- STR
Pset_BeamCommon - Slope: 0 deg; Reference: 40x80 cm; Span: 12.7 m
Pset_QuantityTakeOff - Reference: 40x80 cm; sets with these values: 2
Name (STR- V- Formigó- Rectangular- T1:40x80 cm:...)
41191
41193

# IfcBeam: STR- V- Formigó- Rectangular- T1:70x59 cm, STR- V- Formigó- Rectangular- T1:70x59 cm:41174
In: P0- Escola
Type - PredefinedType: BEAM; Material: _Formigó- T1- STR
Type - Pset_BeamCommon - IsExternal: no; LoadBearing: yes
Pset_BeamCommon - Slope: 0 deg; Reference: 70x59 cm; Span: 23.975 m
Pset_QuantityTakeOff - Reference: 70x59 cm; sets with these values: 2

# IfcBuildingElementProxy: Borde de losa:STR- Formigó- Vora solera 15 cm- 35x30 cm (27)
Pset_BuildingElementProxyCommon - Reference: STR- Formigó- Vora solera 15 cm- 35x30 cm; sets with these values: 2
Name (Borde de losa:STR- Formigó- Vora solera 15 cm- 35x30 cm:...) | In | Group
42431 | PS1- Gimnàs | Grupo de modelo:STR- conjunt soleres:41868
42432 | PS1- Gimnàs | Grupo de modelo:STR- conjunt soleres:41868
42433 | PS1- Gimnàs | Grupo de modelo:STR- conjunt soleres:41868
42434 | PS1- Gimnàs | Grupo de modelo:STR- conjunt soleres:41868 | Pset_ProvisionForVoid - Shape: Undefined
42435 | PS1- Gimnàs | Grupo de modelo:STR- conjunt soleres:41868 | Pset_ProvisionForVoid - Shape: Undefined
42436 | PS1- Vestuari
42449 | PS1- Vestuari
42498 | PS1- Vestuari | Grupo de modelo:STR- Solera interior:42497
42501 | PS1- Vestuari | Grupo de modelo:STR- Solera interior:42497
42502 | PS1- Vestuari | Grupo de modelo:STR- Solera interior:42497
42504 | PS1- Vestuari | Grupo de modelo:STR- Solera interior:42497
42506 | PS1- Vestuari | Grupo de modelo:STR- Solera pati:41579
42507 | PS1- Vestuari | Grupo de modelo:STR- Solera pati:41579 | Pset_ProvisionForVoid - Shape: Undefined
42508 | PS1- Vestuari | Grupo de modelo:STR- Solera pati:41579 | Pset_ProvisionForVoid - Shape: Undefined
42509 | PS1- Vestuari | Grupo de modelo:STR- Solera pati:41579 | Pset_ProvisionForVoid - Shape: Undefined
42510 | PS1- Vestuari | Grupo de modelo:STR- Solera pati:41579
42511 | PS1- Vestuari | Grupo de modelo:STR- Solera pati:41579
42512 | PS1- Vestuari | Grupo de modelo:STR- Solera pati:41579
42513 | PS1- Vestuari | Grupo de modelo:STR- Solera pati:41579
42514 | PS1- Vestuari | Grupo de modelo:STR- Solera pati:41579
42515 | PS1- Vestuari | Grupo de modelo:STR- Solera pati:41579
42516 | PS1- Vestuari | Grupo de modelo:STR- Solera pati:41579
42517 | PS1- Vestuari | Grupo de modelo:STR- Solera pati:41579
42518 | PS1- Gimnàs | Grupo de modelo:STR- conjunt soleres:41868 | Pset_ProvisionForVoid - Shape: Undefined
42519 | PS1- Gimnàs | Grupo de modelo:STR- conjunt soleres:41868
42520 | PS1- Gimnàs | Grupo de modelo:STR- conjunt soleres:41868
42521 | PS1- Gimnàs | Grupo de modelo:STR- conjunt soleres:41868 | Pset_ProvisionForVoid - Shape: Undefined

# IfcBuildingElementProxy: EscalaExterior:EscalaExterior (2)
In: PS1- Vestuari
Type - Material: _Acer- STR
Pset_BuildingElementProxyCommon - Reference: EscalaExterior; sets with these values: 2
Name (EscalaExterior:EscalaExterior:...)
43299
43301

# IfcBuildingElementProxy: STR- S- Formigó- Mur biblio:STR- S- Formigó- Mur biblio, STR- S- Formigó- Mur biblio:STR- S- Formigó- Mur biblio:41936
In: PS1- Gimnàs
Type - Material: _Formigó Pobre- T1- STR, _Formigó- T1- STR
Pset_BuildingElementProxyCommon - Reference: STR- S- Formigó- Mur biblio; sets with these values: 2
Pset_ProvisionForVoid - Width: 5.35746 m; Height: 1.4 m; Depth: 1.4 m

# IfcColumn: STR- P- Acer- CHS- Circular- T1:60.3 x 3CHS (12)
In: P0- Escola
Type - PredefinedType: COLUMN; Material: Metal - Acero - 345 MPa
Type - Pset_ColumnCommon - IsExternal: no; LoadBearing: yes
Pset_ColumnCommon - Reference: 60.3 x 3CHS
Pset_QuantityTakeOff - Reference: 60.3 x 3CHS; sets with these values: 2
Name (STR- P- Acer- CHS- Circular- T1:60.3 x 3CHS:...) | Group
84625 | Grupo de modelo:STR- Pergola pati infantil:84624
84629 | Grupo de modelo:STR- Pergola pati infantil:84624
84631 | Grupo de modelo:STR- Pergola pati infantil:84624
84666 | Grupo de modelo:STR- Pergola pati infantil:84665
84670 | Grupo de modelo:STR- Pergola pati infantil:84665
84672 | Grupo de modelo:STR- Pergola pati infantil:84665
84707 | Grupo de modelo:STR- Pergola pati infantil:84706
84711 | Grupo de modelo:STR- Pergola pati infantil:84706
84713 | Grupo de modelo:STR- Pergola pati infantil:84706
84748 | Grupo de modelo:STR- Pergola pati infantil:84747
84752 | Grupo de modelo:STR- Pergola pati infantil:84747
84754 | Grupo de modelo:STR- Pergola pati infantil:84747

# IfcColumn: STR- P- Acer- HEB- T1:HEB 240, STR- P- Acer- HEB- T1:HEB 240:106512
In: PC- Coberta STR
Type - PredefinedType: COLUMN; Material: _Acer- STR
Type - Pset_ColumnCommon - IsExternal: no; LoadBearing: yes
Pset_ColumnCommon - Reference: HEB 240
Pset_QuantityTakeOff - Reference: HEB 240; sets with these values: 2

# IfcColumn: STR- P- Formigó- Rectangular- T1:25x45cm (2)
In: P0- Escola
Type - PredefinedType: COLUMN; Material: _Formigó- T1- STR
Type - Pset_ColumnCommon - IsExternal: no; LoadBearing: yes
Pset_ColumnCommon - Reference: 25x45cm; Slope: 0 deg
Pset_QuantityTakeOff - Reference: 25x45cm; sets with these values: 2
Name (STR- P- Formigó- Rectangular- T1:25x45cm:...)
41045
43297

# IfcColumn: STR- P- Formigó- Rectangular- T1:25x90cm (30)
In: P0- Escola
Type - PredefinedType: COLUMN; Material: _Formigó- T1- STR
Type - Pset_ColumnCommon - IsExternal: no; LoadBearing: yes
Pset_ColumnCommon - Slope: 0 deg; Reference: 25x90cm
Pset_QuantityTakeOff - Reference: 25x90cm; sets with these values: 2
Name (STR- P- Formigó- Rectangular- T1:25x90cm:...)
41085
41087
41089
41091
41093
41095
41097
41099
41101
41103
41105
41107
41109
41111
41113
41115
41117
41119
41121
41123
41125
41127
41129
41131
41133
41135
41137
41139
41141
41143

# IfcColumn: STR- P- Formigó- Rectangular- T1:30x45cm (27)
Type - PredefinedType: COLUMN; Material: _Formigó- T1- STR
Type - Pset_ColumnCommon - IsExternal: no; LoadBearing: yes
Pset_ColumnCommon - Reference: 30x45cm
Pset_QuantityTakeOff - Reference: 30x45cm; sets with these values: 2
Name (STR- P- Formigó- Rectangular- T1:30x45cm:...) | In | Slope (deg)
41047 | P0- Escola
41049 | P0- Escola | 1.36393
41051 | P0- Escola | 1.36393
41053 | P0- Escola | 1.36393
41055 | P0- Escola | 1.36393
41057 | P0- Escola | 1.36393
41059 | P0- Escola | 1.36393
41061 | P0- Escola | 1.36393
41063 | P0- Escola | 1.36393
41065 | P0- Escola | 0
41067 | P0- Escola | 0
41069 | P0- Escola | 0
41071 | P0- Escola | 0
41073 | P0- Escola | 0
41075 | P0- Escola | 0
41077 | P0- Escola | 0
41079 | P0- Escola | 0
41472 | PS1- Gimnàs | 1.14576
41474 | PS1- Gimnàs | 0
41477 | PS1- Gimnàs | 4.57361
41512 | PS1- Vestuari
41514 | PS1- Vestuari
41516 | PS1- Vestuari
41518 | PS1- Vestuari
41520 | PS1- Vestuari
41522 | PS1- Gimnàs | 4.57392
41524 | PS1- Gimnàs | 4.57361

# IfcColumn: STR- P- Formigó- Rectangular- T1:30x80 cm (2)
In: PS1- Vestuari
Type - PredefinedType: COLUMN; Material: _Formigó- T1- STR
Type - Pset_ColumnCommon - IsExternal: no; LoadBearing: yes
Pset_ColumnCommon - Reference: 30x80 cm
Pset_QuantityTakeOff - Reference: 30x80 cm; sets with these values: 2
Name (STR- P- Formigó- Rectangular- T1:30x80 cm:...)
41918
41920

# IfcColumn: STR- P- Formigó- Rectangular- T1:40x70cm (7)
Type - PredefinedType: COLUMN; Material: _Formigó- T1- STR
Type - Pset_ColumnCommon - IsExternal: no; LoadBearing: yes
Pset_ColumnCommon - Reference: 40x70cm
Pset_QuantityTakeOff - Reference: 40x70cm; sets with these values: 2
Name (STR- P- Formigó- Rectangular- T1:40x70cm:...) | In | Slope (deg)
41081 | P0- Escola | 0
41083 | P0- Escola | 0
41301 | PS1- Gimnàs
41378 | PS1- Gimnàs
41380 | PS1- Gimnàs
41382 | PS1- Gimnàs | 0
41384 | PS1- Gimnàs | 0

# IfcColumn: STR- P- Pantalla formigó component:STR- P- Pantalla formigó component, STR- P- Pantalla formigó component:STR- P- Pantalla formigó component:41281
In: PS1- Gimnàs
Type - PredefinedType: COLUMN; Material: _Formigó- T1- STR
Type - Pset_ColumnCommon - IsExternal: no; LoadBearing: yes
Pset_ColumnCommon - Reference: STR- P- Pantalla formigó component
Pset_QuantityTakeOff - Reference: STR- P- Pantalla formigó component; sets with these values: 2

# IfcFooting: Cimentación de muro:STR- S- Formigó- Sabata 80- m30-h45 (11)
In: PS1- Vestuari
PredefinedType: STRIP_FOOTING; Material: _Formigó- T1- STR
Pset_QuantityTakeOff - Reference: STR- S- Formigó- Sabata 80- m30-h45; sets with these values: 3
Name (Cimentación de muro:STR- S- Formigó- Sabata 80- m30-h45:...) | Group
42621 | Grupo de modelo:Mp-6 2:42619
42623 | Grupo de modelo:Mp-6 2:42619
42625 | Grupo de modelo:Mp-6 2:42619
42627 | Grupo de modelo:Mp-6 2:42619
42629 | Grupo de modelo:Mp-6 2:42619
42631 | Grupo de modelo:Mp-6 2:42619
42633 | Grupo de modelo:Mp-6 2:42619
42674 | Grupo de modelo:Mp-6 2:42619
42676 | Grupo de modelo:Mp-6 2:42619
42678 | Grupo de modelo:Mp-6 2:42619
114059

# IfcFooting: Cimentación de muro:STR- S- Formigó- Sabata 80- m30-h50 (2)
In: PS1- Vestuari
PredefinedType: STRIP_FOOTING; Material: _Formigó- T1- STR; Group: Grupo de modelo:Mp-6 2:42619
Pset_QuantityTakeOff - Reference: STR- S- Formigó- Sabata 80- m30-h50; sets with these values: 3
Name (Cimentación de muro:STR- S- Formigó- Sabata 80- m30-h50:...)
42683
42685

# IfcFooting: Cimentación de muro:STR- S- Formigó- Sabata MP -1 i 2 m (21)
PredefinedType: STRIP_FOOTING; Material: _Formigó- T1- STR
Pset_QuantityTakeOff - Reference: STR- S- Formigó- Sabata MP -1 i 2 m; sets with these values: 3
Name (Cimentación de muro:STR- S- Formigó- Sabata MP -1 i 2 m:...) | In
43094 | PS1- Gimnàs | Group: Grupo de modelo:Murs urbanització 2:43208
43143 | PS1- Vestuari | Group: Grupo de modelo:Murs urbanització 2:43208
113455 | PS1- Vestuari
113457 | PS1- Vestuari
113459 | PS1- Vestuari
113461 | PS1- Vestuari
113463 | P0- Escola
113465 | P0- Escola
113467 | P0- Escola
113469 | P0- Escola
113471 | P0- Escola
113473 | P0- Escola
113475 | PS1- Vestuari
113477 | PS1- Vestuari
113479 | PS1- Vestuari
113481 | P0- Escola
113483 | P0- Escola
113485 | P0- Escola
113487 | P0- Escola
113489 | P0- Escola
113491 | P0- Escola

# IfcFooting: Cimentación de muro:STR- S- Formigó- Sabata MP -1 m (8)
In: PS1- Gimnàs
PredefinedType: STRIP_FOOTING; Material: _Formigó- T1- STR; Group: Grupo de modelo:Murs urbanització 2:43208
Pset_QuantityTakeOff - Reference: STR- S- Formigó- Sabata MP -1 m; sets with these values: 3
Name (Cimentación de muro:STR- S- Formigó- Sabata MP -1 m:...)
43089
43091
43097
43100
43104
43107
43110
43117

# IfcFooting: Cimentación de muro:STR- S- Formigó- Sabata MP1 +2m (12)
PredefinedType: STRIP_FOOTING; Material: _Formigó- T1- STR; Group: Grupo de modelo:Murs urbanització 2:43208
Pset_QuantityTakeOff - Reference: STR- S- Formigó- Sabata MP1 +2m; sets with these values: 3
Name (Cimentación de muro:STR- S- Formigó- Sabata MP1 +2m:...) | In
43087 | PS1- Gimnàs
43113 | PS1- Gimnàs
43115 | PS1- Gimnàs
43120 | PS1- Gimnàs
43123 | PS1- Gimnàs
43128 | PS1- Vestuari
43130 | PS1- Vestuari
43133 | PS1- Vestuari
43136 | PS1- Gimnàs
43139 | PS1- Gimnàs
43141 | PS1- Gimnàs
43146 | PS1- Gimnàs

# IfcFooting: Cimentación de muro:STR- S- Formigó- Sabata mur 100 T-30, Cimentación de muro:STR- S- Formigó- Sabata mur 100 T-30:42217
In: PS1- Gimnàs
PredefinedType: STRIP_FOOTING; Material: _Formigó- T1- STR
Pset_QuantityTakeOff - Reference: STR- S- Formigó- Sabata mur 100 T-30; sets with these values: 3

# IfcFooting: Cimentación de muro:STR- S- Formigó- Sabata mur 100 T-54 (7)
In: PS1- Gimnàs
PredefinedType: STRIP_FOOTING; Material: _Formigó- T1- STR
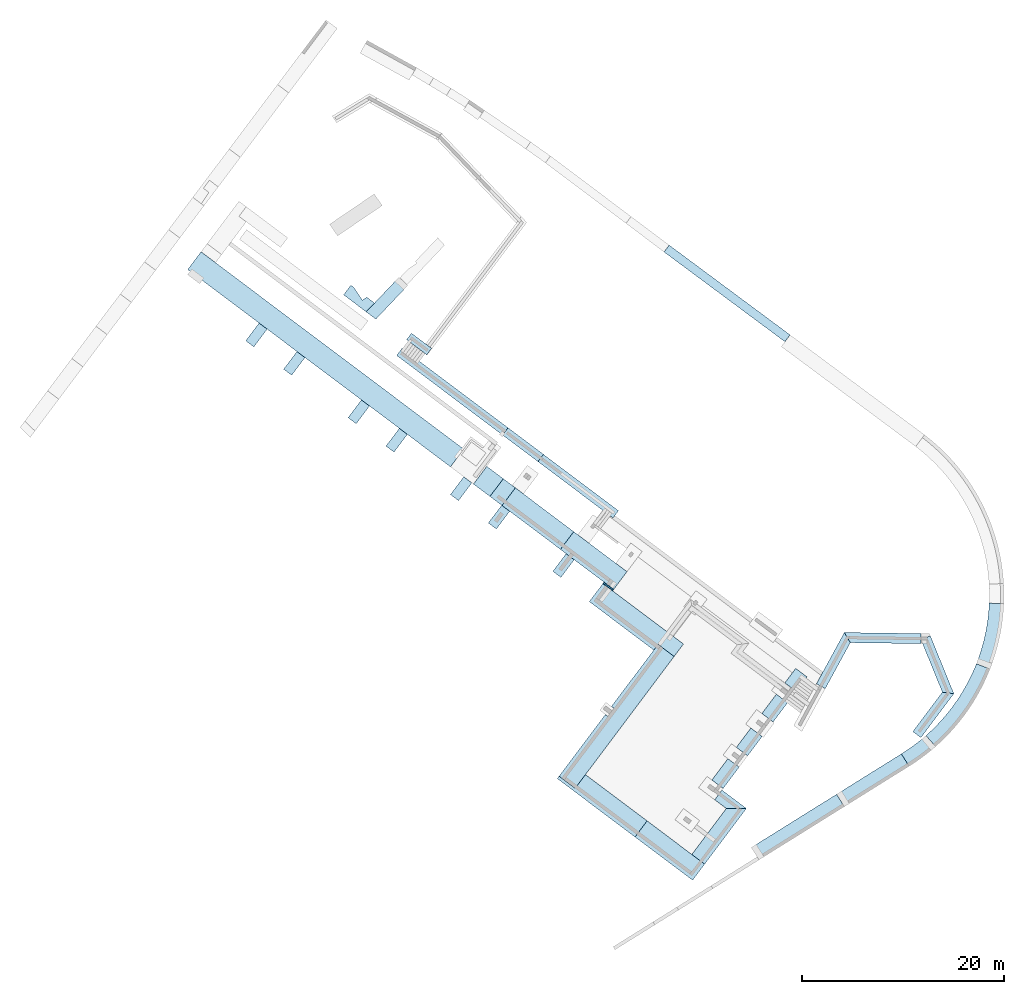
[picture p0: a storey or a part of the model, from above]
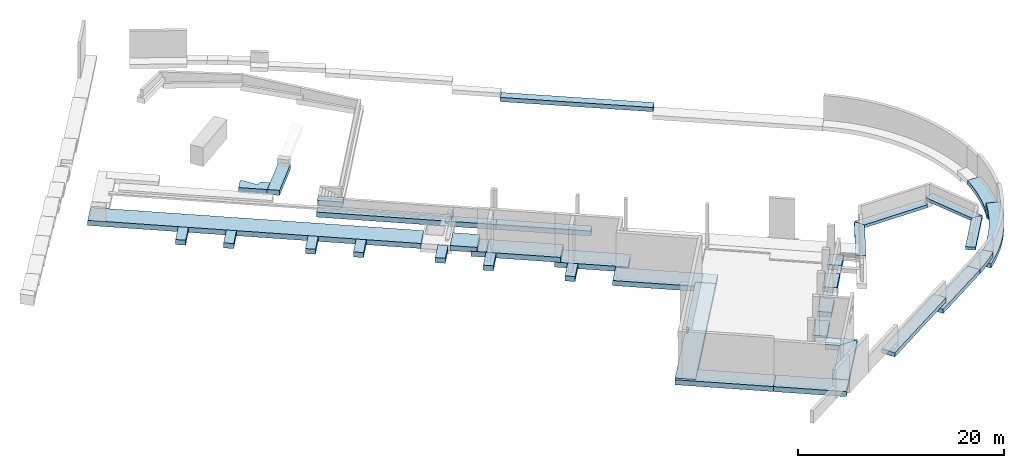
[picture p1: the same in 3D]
Properties of the parts of a building model (IFC2X3), part 2 of 3

# IfcFooting: Cimentación de muro:STR- S- Formigó- Sabata mur 100 T-54 (7)
Pset_QuantityTakeOff - Reference: STR- S- Formigó- Sabata mur 100 T-54; sets with these values: 3
Name (Cimentación de muro:STR- S- Formigó- Sabata mur 100 T-54:...)
41769
41775
41781
41787
41793
41873
42020

# IfcFooting: Cimentación de muro:STR- S- Formigó- Sabata mur 100- M30- H45 (4)
In: PS1- Gimnàs
PredefinedType: STRIP_FOOTING; Material: _Formigó- T1- STR
Pset_QuantityTakeOff - Reference: STR- S- Formigó- Sabata mur 100- M30- H45; sets with these values: 3
Name (Cimentación de muro:STR- S- Formigó- Sabata mur 100- M30- H45:...)
41961
41963
41965
41967

# IfcFooting: Cimentación de muro:STR- S- Formigó- Sabata mur 110- T1, Cimentación de muro:STR- S- Formigó- Sabata mur 110- T1:42402
In: PS1- Vestuari
PredefinedType: STRIP_FOOTING; Material: _Formigó- T1- STR
Pset_QuantityTakeOff - Reference: STR- S- Formigó- Sabata mur 110- T1; sets with these values: 3

# IfcFooting: Cimentación de muro:STR- S- Formigó- Sabata mur 120 (4)
In: PS1- Gimnàs
PredefinedType: STRIP_FOOTING; Material: _Formigó- T1- STR
Pset_QuantityTakeOff - Reference: STR- S- Formigó- Sabata mur 120; sets with these values: 3
Name (Cimentación de muro:STR- S- Formigó- Sabata mur 120:...)
41811
41813
42221
42389

# IfcFooting: Cimentación de muro:STR- S- Formigó- Sabata mur 120 t2, Cimentación de muro:STR- S- Formigó- Sabata mur 120 t2:41844
In: PS1- Gimnàs
PredefinedType: STRIP_FOOTING; Material: _Formigó- T1- STR
Pset_QuantityTakeOff - Reference: STR- S- Formigó- Sabata mur 120 t2; sets with these values: 3

# IfcFooting: Cimentación de muro:STR- S- Formigó- Sabata mur 120 t3, Cimentación de muro:STR- S- Formigó- Sabata mur 120 t3:42594
In: PS1- Gimnàs
PredefinedType: STRIP_FOOTING; Material: _Formigó- T1- STR
Pset_QuantityTakeOff - Reference: STR- S- Formigó- Sabata mur 120 t3; sets with these values: 3

# IfcFooting: Cimentación de muro:STR- S- Formigó- Sabata mur 130 t2 2, Cimentación de muro:STR- S- Formigó- Sabata mur 130 t2 2:42404
In: PS1- Vestuari
PredefinedType: STRIP_FOOTING; Material: _Formigó- T1- STR
Pset_QuantityTakeOff - Reference: STR- S- Formigó- Sabata mur 130 t2 2; sets with these values: 3

# IfcFooting: Cimentación de muro:STR- S- Formigó- Sabata mur 140- t30 (2)
In: PS1- Gimnàs
PredefinedType: STRIP_FOOTING; Material: _Formigó- T1- STR
Pset_QuantityTakeOff - Reference: STR- S- Formigó- Sabata mur 140- t30; sets with these values: 3
Name (Cimentación de muro:STR- S- Formigó- Sabata mur 140- t30:...)
41846
43229

# IfcFooting: Cimentación de muro:STR- S- Formigó- Sabata mur 150 t3, Cimentación de muro:STR- S- Formigó- Sabata mur 150 t3:42406
In: PS1- Vestuari
PredefinedType: STRIP_FOOTING; Material: _Formigó- T1- STR
Pset_QuantityTakeOff - Reference: STR- S- Formigó- Sabata mur 150 t3; sets with these values: 3

# IfcFooting: Cimentación de muro:STR- S- Formigó- Sabata mur 160, Cimentación de muro:STR- S- Formigó- Sabata mur 160:41842
In: PS1- Gimnàs
PredefinedType: STRIP_FOOTING; Material: _Formigó- T1- STR
Pset_QuantityTakeOff - Reference: STR- S- Formigó- Sabata mur 160; sets with these values: 3

# IfcFooting: Cimentación de muro:STR- S- Formigó- Sabata mur 180 (2)
In: PS1- Gimnàs
PredefinedType: STRIP_FOOTING; Material: _Formigó- T1- STR
Pset_QuantityTakeOff - Reference: STR- S- Formigó- Sabata mur 180; sets with these values: 3
Name (Cimentación de muro:STR- S- Formigó- Sabata mur 180:...)
42409
42415

# IfcFooting: Cimentación de muro:STR- S- Formigó- Sabata mur 200, Cimentación de muro:STR- S- Formigó- Sabata mur 200:41840
In: PS1- Gimnàs
PredefinedType: STRIP_FOOTING; Material: _Formigó- T1- STR
Pset_QuantityTakeOff - Reference: STR- S- Formigó- Sabata mur 200; sets with these values: 3

# IfcFooting: Cimentación de muro:STR- S- Formigó- Sabata mur 200 T2 (2)
In: PS1- Gimnàs
PredefinedType: STRIP_FOOTING; Material: _Formigó- T1- STR
Pset_QuantityTakeOff - Reference: STR- S- Formigó- Sabata mur 200 T2; sets with these values: 3
Name (Cimentación de muro:STR- S- Formigó- Sabata mur 200 T2:...)
41836
41838

# IfcFooting: Cimentación de muro:STR- S- Formigó- Sabata mur 220 (6)
In: PS1- Gimnàs
PredefinedType: STRIP_FOOTING; Material: _Formigó- T1- STR
Pset_QuantityTakeOff - Reference: STR- S- Formigó- Sabata mur 220; sets with these values: 3
Name (Cimentación de muro:STR- S- Formigó- Sabata mur 220:...)
41869
41871
41879
42354
42358
42360

# IfcFooting: Cimentación de muro:STR- S- Formigó- Sabata mur 60, Cimentación de muro:STR- S- Formigó- Sabata mur 60:42225
In: PS1- Vestuari
PredefinedType: STRIP_FOOTING; Material: _Formigó- T1- STR
Pset_QuantityTakeOff - Reference: STR- S- Formigó- Sabata mur 60; sets with these values: 3

# IfcFooting: Cimentación de muro:STR- S- Formigó- Sabata mur 60 mur 20 (3)
In: PS1- Vestuari
PredefinedType: STRIP_FOOTING; Material: _Formigó- T1- STR
Pset_QuantityTakeOff - Reference: STR- S- Formigó- Sabata mur 60 mur 20; sets with these values: 3
Name (Cimentación de muro:STR- S- Formigó- Sabata mur 60 mur 20:...)
42231
42233
42235

# IfcFooting: Cimentación de muro:STR- S- Formigó- Sabata mur 80 (6)
In: PS1- Gimnàs
PredefinedType: STRIP_FOOTING; Material: _Formigó- T1- STR
Pset_QuantityTakeOff - Reference: STR- S- Formigó- Sabata mur 80; sets with these values: 3
Name (Cimentación de muro:STR- S- Formigó- Sabata mur 80:...)
42178
42192
42195
42198
42201
154746

# IfcFooting: Cimentación de muro:STR- S- Formigó- Sabata mur 90 (4)
PredefinedType: STRIP_FOOTING; Material: _Formigó- T1- STR
Pset_QuantityTakeOff - Reference: STR- S- Formigó- Sabata mur 90; sets with these values: 3
Name (Cimentación de muro:STR- S- Formigó- Sabata mur 90:...) | In
41893 | PS1- Gimnàs
42098 | PS1- Gimnàs
42157 | PS1- Gimnàs
42400 | PS1- Vestuari

# IfcGroup: Grupo de modelo:Grupo de matriz 3 (448)
Name (Grupo de modelo:Grupo de matriz 3:...) | Group
177522 | Grupo de modelo:Grupo de matriz 4:177664
177527 | Grupo de modelo:Grupo de matriz 4:177664
177551 | Grupo de modelo:Grupo de matriz 4:177664
177555 | Grupo de modelo:Grupo de matriz 4:177664
177559 | Grupo de modelo:Grupo de matriz 4:177664
177563 | Grupo de modelo:Grupo de matriz 4:177664
177567 | Grupo de modelo:Grupo de matriz 4:177664
177571 | Grupo de modelo:Grupo de matriz 4:177664
177575 | Grupo de modelo:Grupo de matriz 4:177664
177579 | Grupo de modelo:Grupo de matriz 4:177664
177583 | Grupo de modelo:Grupo de matriz 4:177664
177587 | Grupo de modelo:Grupo de matriz 4:177664
177591 | Grupo de modelo:Grupo de matriz 4:177664
177595 | Grupo de modelo:Grupo de matriz 4:177664
177599 | Grupo de modelo:Grupo de matriz 4:177664
177659 | Grupo de modelo:Grupo de matriz 4:177664
177675 | Grupo de modelo:Grupo de matriz 4:177725
177678 | Grupo de modelo:Grupo de matriz 4:177725
177685 | Grupo de modelo:Grupo de matriz 4:177725
177688 | Grupo de modelo:Grupo de matriz 4:177725
177691 | Grupo de modelo:Grupo de matriz 4:177725
177694 | Grupo de modelo:Grupo de matriz 4:177725
177697 | Grupo de modelo:Grupo de matriz 4:177725
177700 | Grupo de modelo:Grupo de matriz 4:177725
177703 | Grupo de modelo:Grupo de matriz 4:177725
177706 | Grupo de modelo:Grupo de matriz 4:177725
177709 | Grupo de modelo:Grupo de matriz 4:177725
177712 | Grupo de modelo:Grupo de matriz 4:177725
177715 | Grupo de modelo:Grupo de matriz 4:177725
177718 | Grupo de modelo:Grupo de matriz 4:177725
177721 | Grupo de modelo:Grupo de matriz 4:177725
177724 | Grupo de modelo:Grupo de matriz 4:177725
181538 | Grupo de modelo:Grupo de matriz 4:181588
181541 | Grupo de modelo:Grupo de matriz 4:181588
181548 | Grupo de modelo:Grupo de matriz 4:181588
181551 | Grupo de modelo:Grupo de matriz 4:181588
181554 | Grupo de modelo:Grupo de matriz 4:181588
181557 | Grupo de modelo:Grupo de matriz 4:181588
181560 | Grupo de modelo:Grupo de matriz 4:181588
181563 | Grupo de modelo:Grupo de matriz 4:181588
181566 | Grupo de modelo:Grupo de matriz 4:181588
181569 | Grupo de modelo:Grupo de matriz 4:181588
181572 | Grupo de modelo:Grupo de matriz 4:181588
181575 | Grupo de modelo:Grupo de matriz 4:181588
181578 | Grupo de modelo:Grupo de matriz 4:181588
181581 | Grupo de modelo:Grupo de matriz 4:181588
181584 | Grupo de modelo:Grupo de matriz 4:181588
181587 | Grupo de modelo:Grupo de matriz 4:181588
181591 | Grupo de modelo:Grupo de matriz 4:181641
181594 | Grupo de modelo:Grupo de matriz 4:181641
181601 | Grupo de modelo:Grupo de matriz 4:181641
181604 | Grupo de modelo:Grupo de matriz 4:181641
181607 | Grupo de modelo:Grupo de matriz 4:181641
181610 | Grupo de modelo:Grupo de matriz 4:181641
181613 | Grupo de modelo:Grupo de matriz 4:181641
181616 | Grupo de modelo:Grupo de matriz 4:181641
181619 | Grupo de modelo:Grupo de matriz 4:181641
181622 | Grupo de modelo:Grupo de matriz 4:181641
181625 | Grupo de modelo:Grupo de matriz 4:181641
181628 | Grupo de modelo:Grupo de matriz 4:181641
181631 | Grupo de modelo:Grupo de matriz 4:181641
181634 | Grupo de modelo:Grupo de matriz 4:181641
181637 | Grupo de modelo:Grupo de matriz 4:181641
181640 | Grupo de modelo:Grupo de matriz 4:181641
182020 | Grupo de modelo:Grupo de matriz 4:182070
182023 | Grupo de modelo:Grupo de matriz 4:182070
182030 | Grupo de modelo:Grupo de matriz 4:182070
182033 | Grupo de modelo:Grupo de matriz 4:182070
182036 | Grupo de modelo:Grupo de matriz 4:182070
182039 | Grupo de modelo:Grupo de matriz 4:182070
182042 | Grupo de modelo:Grupo de matriz 4:182070
182045 | Grupo de modelo:Grupo de matriz 4:182070
182048 | Grupo de modelo:Grupo de matriz 4:182070
182051 | Grupo de modelo:Grupo de matriz 4:182070
182054 | Grupo de modelo:Grupo de matriz 4:182070
182057 | Grupo de modelo:Grupo de matriz 4:182070
182060 | Grupo de modelo:Grupo de matriz 4:182070
182063 | Grupo de modelo:Grupo de matriz 4:182070
182066 | Grupo de modelo:Grupo de matriz 4:182070
182069 | Grupo de modelo:Grupo de matriz 4:182070
182073 | Grupo de modelo:Grupo de matriz 4:182123
182076 | Grupo de modelo:Grupo de matriz 4:182123
182083 | Grupo de modelo:Grupo de matriz 4:182123
182086 | Grupo de modelo:Grupo de matriz 4:182123
182089 | Grupo de modelo:Grupo de matriz 4:182123
182092 | Grupo de modelo:Grupo de matriz 4:182123
182095 | Grupo de modelo:Grupo de matriz 4:182123
182098 | Grupo de modelo:Grupo de matriz 4:182123
182101 | Grupo de modelo:Grupo de matriz 4:182123
182104 | Grupo de modelo:Grupo de matriz 4:182123
182107 | Grupo de modelo:Grupo de matriz 4:182123
182110 | Grupo de modelo:Grupo de matriz 4:182123
182113 | Grupo de modelo:Grupo de matriz 4:182123
182116 | Grupo de modelo:Grupo de matriz 4:182123
182119 | Grupo de modelo:Grupo de matriz 4:182123
182122 | Grupo de modelo:Grupo de matriz 4:182123
182502 | Grupo de modelo:Grupo de matriz 4:182552
182505 | Grupo de modelo:Grupo de matriz 4:182552
182512 | Grupo de modelo:Grupo de matriz 4:182552
182515 | Grupo de modelo:Grupo de matriz 4:182552
182518 | Grupo de modelo:Grupo de matriz 4:182552
182521 | Grupo de modelo:Grupo de matriz 4:182552
182524 | Grupo de modelo:Grupo de matriz 4:182552
182527 | Grupo de modelo:Grupo de matriz 4:182552
182530 | Grupo de modelo:Grupo de matriz 4:182552
182533 | Grupo de modelo:Grupo de matriz 4:182552
182536 | Grupo de modelo:Grupo de matriz 4:182552
182539 | Grupo de modelo:Grupo de matriz 4:182552
182542 | Grupo de modelo:Grupo de matriz 4:182552
182545 | Grupo de modelo:Grupo de matriz 4:182552
182548 | Grupo de modelo:Grupo de matriz 4:182552
182551 | Grupo de modelo:Grupo de matriz 4:182552
182555 | Grupo de modelo:Grupo de matriz 4:182605
182558 | Grupo de modelo:Grupo de matriz 4:182605
182565 | Grupo de modelo:Grupo de matriz 4:182605
182568 | Grupo de modelo:Grupo de matriz 4:182605
182571 | Grupo de modelo:Grupo de matriz 4:182605
182574 | Grupo de modelo:Grupo de matriz 4:182605
182577 | Grupo de modelo:Grupo de matriz 4:182605
182580 | Grupo de modelo:Grupo de matriz 4:182605
182583 | Grupo de modelo:Grupo de matriz 4:182605
182586 | Grupo de modelo:Grupo de matriz 4:182605
182589 | Grupo de modelo:Grupo de matriz 4:182605
182592 | Grupo de modelo:Grupo de matriz 4:182605
182595 | Grupo de modelo:Grupo de matriz 4:182605
182598 | Grupo de modelo:Grupo de matriz 4:182605
182601 | Grupo de modelo:Grupo de matriz 4:182605
182604 | Grupo de modelo:Grupo de matriz 4:182605
190969 | Grupo de modelo:Grupo de matriz 4:191019
190972 | Grupo de modelo:Grupo de matriz 4:191019
190979 | Grupo de modelo:Grupo de matriz 4:191019
190982 | Grupo de modelo:Grupo de matriz 4:191019
190985 | Grupo de modelo:Grupo de matriz 4:191019
190988 | Grupo de modelo:Grupo de matriz 4:191019
190991 | Grupo de modelo:Grupo de matriz 4:191019
190994 | Grupo de modelo:Grupo de matriz 4:191019
190997 | Grupo de modelo:Grupo de matriz 4:191019
191000 | Grupo de modelo:Grupo de matriz 4:191019
191003 | Grupo de modelo:Grupo de matriz 4:191019
191006 | Grupo de modelo:Grupo de matriz 4:191019
191009 | Grupo de modelo:Grupo de matriz 4:191019
191012 | Grupo de modelo:Grupo de matriz 4:191019
191015 | Grupo de modelo:Grupo de matriz 4:191019
191018 | Grupo de modelo:Grupo de matriz 4:191019
191022 | Grupo de modelo:Grupo de matriz 4:191072
191025 | Grupo de modelo:Grupo de matriz 4:191072
191032 | Grupo de modelo:Grupo de matriz 4:191072
191035 | Grupo de modelo:Grupo de matriz 4:191072
191038 | Grupo de modelo:Grupo de matriz 4:191072
191041 | Grupo de modelo:Grupo de matriz 4:191072
191044 | Grupo de modelo:Grupo de matriz 4:191072
191047 | Grupo de modelo:Grupo de matriz 4:191072
191050 | Grupo de modelo:Grupo de matriz 4:191072
191053 | Grupo de modelo:Grupo de matriz 4:191072
191056 | Grupo de modelo:Grupo de matriz 4:191072
191059 | Grupo de modelo:Grupo de matriz 4:191072
191062 | Grupo de modelo:Grupo de matriz 4:191072
191065 | Grupo de modelo:Grupo de matriz 4:191072
191068 | Grupo de modelo:Grupo de matriz 4:191072
191071 | Grupo de modelo:Grupo de matriz 4:191072
191075 | Grupo de modelo:Grupo de matriz 4:191125
191078 | Grupo de modelo:Grupo de matriz 4:191125
191085 | Grupo de modelo:Grupo de matriz 4:191125
191088 | Grupo de modelo:Grupo de matriz 4:191125
191091 | Grupo de modelo:Grupo de matriz 4:191125
191094 | Grupo de modelo:Grupo de matriz 4:191125
191097 | Grupo de modelo:Grupo de matriz 4:191125
191100 | Grupo de modelo:Grupo de matriz 4:191125
191103 | Grupo de modelo:Grupo de matriz 4:191125
191106 | Grupo de modelo:Grupo de matriz 4:191125
191109 | Grupo de modelo:Grupo de matriz 4:191125
191112 | Grupo de modelo:Grupo de matriz 4:191125
191115 | Grupo de modelo:Grupo de matriz 4:191125
191118 | Grupo de modelo:Grupo de matriz 4:191125
191121 | Grupo de modelo:Grupo de matriz 4:191125
191124 | Grupo de modelo:Grupo de matriz 4:191125
191128 | Grupo de modelo:Grupo de matriz 4:191178
191131 | Grupo de modelo:Grupo de matriz 4:191178
191138 | Grupo de modelo:Grupo de matriz 4:191178
191141 | Grupo de modelo:Grupo de matriz 4:191178
191144 | Grupo de modelo:Grupo de matriz 4:191178
191147 | Grupo de modelo:Grupo de matriz 4:191178
191150 | Grupo de modelo:Grupo de matriz 4:191178
191153 | Grupo de modelo:Grupo de matriz 4:191178
191156 | Grupo de modelo:Grupo de matriz 4:191178
191159 | Grupo de modelo:Grupo de matriz 4:191178
191162 | Grupo de modelo:Grupo de matriz 4:191178
191165 | Grupo de modelo:Grupo de matriz 4:191178
191168 | Grupo de modelo:Grupo de matriz 4:191178
191171 | Grupo de modelo:Grupo de matriz 4:191178
191174 | Grupo de modelo:Grupo de matriz 4:191178
191177 | Grupo de modelo:Grupo de matriz 4:191178
191181 | Grupo de modelo:Grupo de matriz 4:191231
191184 | Grupo de modelo:Grupo de matriz 4:191231
191191 | Grupo de modelo:Grupo de matriz 4:191231
191194 | Grupo de modelo:Grupo de matriz 4:191231
191197 | Grupo de modelo:Grupo de matriz 4:191231
191200 | Grupo de modelo:Grupo de matriz 4:191231
191203 | Grupo de modelo:Grupo de matriz 4:191231
191206 | Grupo de modelo:Grupo de matriz 4:191231
191209 | Grupo de modelo:Grupo de matriz 4:191231
191212 | Grupo de modelo:Grupo de matriz 4:191231
191215 | Grupo de modelo:Grupo de matriz 4:191231
191218 | Grupo de modelo:Grupo de matriz 4:191231
191221 | Grupo de modelo:Grupo de matriz 4:191231
191224 | Grupo de modelo:Grupo de matriz 4:191231
191227 | Grupo de modelo:Grupo de matriz 4:191231
191230 | Grupo de modelo:Grupo de matriz 4:191231
194079 | Grupo de modelo:Grupo de matriz 4:194129
194082 | Grupo de modelo:Grupo de matriz 4:194129
194089 | Grupo de modelo:Grupo de matriz 4:194129
194092 | Grupo de modelo:Grupo de matriz 4:194129
194095 | Grupo de modelo:Grupo de matriz 4:194129
194098 | Grupo de modelo:Grupo de matriz 4:194129
194101 | Grupo de modelo:Grupo de matriz 4:194129
194104 | Grupo de modelo:Grupo de matriz 4:194129
194107 | Grupo de modelo:Grupo de matriz 4:194129
194110 | Grupo de modelo:Grupo de matriz 4:194129
194113 | Grupo de modelo:Grupo de matriz 4:194129
194116 | Grupo de modelo:Grupo de matriz 4:194129
194119 | Grupo de modelo:Grupo de matriz 4:194129
194122 | Grupo de modelo:Grupo de matriz 4:194129
194125 | Grupo de modelo:Grupo de matriz 4:194129
194128 | Grupo de modelo:Grupo de matriz 4:194129
194132 | Grupo de modelo:Grupo de matriz 4:194182
194135 | Grupo de modelo:Grupo de matriz 4:194182
194142 | Grupo de modelo:Grupo de matriz 4:194182
194145 | Grupo de modelo:Grupo de matriz 4:194182
194148 | Grupo de modelo:Grupo de matriz 4:194182
194151 | Grupo de modelo:Grupo de matriz 4:194182
194154 | Grupo de modelo:Grupo de matriz 4:194182
194157 | Grupo de modelo:Grupo de matriz 4:194182
194160 | Grupo de modelo:Grupo de matriz 4:194182
194163 | Grupo de modelo:Grupo de matriz 4:194182
194166 | Grupo de modelo:Grupo de matriz 4:194182
194169 | Grupo de modelo:Grupo de matriz 4:194182
194172 | Grupo de modelo:Grupo de matriz 4:194182
194175 | Grupo de modelo:Grupo de matriz 4:194182
194178 | Grupo de modelo:Grupo de matriz 4:194182
194181 | Grupo de modelo:Grupo de matriz 4:194182
194185 | Grupo de modelo:Grupo de matriz 4:194235
194188 | Grupo de modelo:Grupo de matriz 4:194235
194195 | Grupo de modelo:Grupo de matriz 4:194235
194198 | Grupo de modelo:Grupo de matriz 4:194235
194201 | Grupo de modelo:Grupo de matriz 4:194235
194204 | Grupo de modelo:Grupo de matriz 4:194235
194207 | Grupo de modelo:Grupo de matriz 4:194235
194210 | Grupo de modelo:Grupo de matriz 4:194235
194213 | Grupo de modelo:Grupo de matriz 4:194235
194216 | Grupo de modelo:Grupo de matriz 4:194235
194219 | Grupo de modelo:Grupo de matriz 4:194235
194222 | Grupo de modelo:Grupo de matriz 4:194235
194225 | Grupo de modelo:Grupo de matriz 4:194235
194228 | Grupo de modelo:Grupo de matriz 4:194235
194231 | Grupo de modelo:Grupo de matriz 4:194235
194234 | Grupo de modelo:Grupo de matriz 4:194235
194238 | Grupo de modelo:Grupo de matriz 4:194288
194241 | Grupo de modelo:Grupo de matriz 4:194288
194248 | Grupo de modelo:Grupo de matriz 4:194288
194251 | Grupo de modelo:Grupo de matriz 4:194288
194254 | Grupo de modelo:Grupo de matriz 4:194288
194257 | Grupo de modelo:Grupo de matriz 4:194288
194260 | Grupo de modelo:Grupo de matriz 4:194288
194263 | Grupo de modelo:Grupo de matriz 4:194288
194266 | Grupo de modelo:Grupo de matriz 4:194288
194269 | Grupo de modelo:Grupo de matriz 4:194288
194272 | Grupo de modelo:Grupo de matriz 4:194288
194275 | Grupo de modelo:Grupo de matriz 4:194288
194278 | Grupo de modelo:Grupo de matriz 4:194288
194281 | Grupo de modelo:Grupo de matriz 4:194288
194284 | Grupo de modelo:Grupo de matriz 4:194288
194287 | Grupo de modelo:Grupo de matriz 4:194288
194291 | Grupo de modelo:Grupo de matriz 4:194341
194294 | Grupo de modelo:Grupo de matriz 4:194341
194301 | Grupo de modelo:Grupo de matriz 4:194341
194304 | Grupo de modelo:Grupo de matriz 4:194341
194307 | Grupo de modelo:Grupo de matriz 4:194341
194310 | Grupo de modelo:Grupo de matriz 4:194341
194313 | Grupo de modelo:Grupo de matriz 4:194341
194316 | Grupo de modelo:Grupo de matriz 4:194341
194319 | Grupo de modelo:Grupo de matriz 4:194341
194322 | Grupo de modelo:Grupo de matriz 4:194341
194325 | Grupo de modelo:Grupo de matriz 4:194341
194328 | Grupo de modelo:Grupo de matriz 4:194341
194331 | Grupo de modelo:Grupo de matriz 4:194341
194334 | Grupo de modelo:Grupo de matriz 4:194341
194337 | Grupo de modelo:Grupo de matriz 4:194341
194340 | Grupo de modelo:Grupo de matriz 4:194341
194398 | Grupo de modelo:Grupo de matriz 4:194448
194401 | Grupo de modelo:Grupo de matriz 4:194448
194408 | Grupo de modelo:Grupo de matriz 4:194448
194411 | Grupo de modelo:Grupo de matriz 4:194448
194414 | Grupo de modelo:Grupo de matriz 4:194448
194417 | Grupo de modelo:Grupo de matriz 4:194448
194420 | Grupo de modelo:Grupo de matriz 4:194448
194423 | Grupo de modelo:Grupo de matriz 4:194448
194426 | Grupo de modelo:Grupo de matriz 4:194448
194429 | Grupo de modelo:Grupo de matriz 4:194448
194432 | Grupo de modelo:Grupo de matriz 4:194448
194435 | Grupo de modelo:Grupo de matriz 4:194448
194438 | Grupo de modelo:Grupo de matriz 4:194448
194441 | Grupo de modelo:Grupo de matriz 4:194448
194444 | Grupo de modelo:Grupo de matriz 4:194448
194447 | Grupo de modelo:Grupo de matriz 4:194448
194451 | Grupo de modelo:Grupo de matriz 4:194501
194454 | Grupo de modelo:Grupo de matriz 4:194501
194461 | Grupo de modelo:Grupo de matriz 4:194501
194464 | Grupo de modelo:Grupo de matriz 4:194501
194467 | Grupo de modelo:Grupo de matriz 4:194501
194470 | Grupo de modelo:Grupo de matriz 4:194501
194473 | Grupo de modelo:Grupo de matriz 4:194501
194476 | Grupo de modelo:Grupo de matriz 4:194501
194479 | Grupo de modelo:Grupo de matriz 4:194501
194482 | Grupo de modelo:Grupo de matriz 4:194501
194485 | Grupo de modelo:Grupo de matriz 4:194501
194488 | Grupo de modelo:Grupo de matriz 4:194501
194491 | Grupo de modelo:Grupo de matriz 4:194501
194494 | Grupo de modelo:Grupo de matriz 4:194501
194497 | Grupo de modelo:Grupo de matriz 4:194501
194500 | Grupo de modelo:Grupo de matriz 4:194501
194504 | Grupo de modelo:Grupo de matriz 4:194554
194507 | Grupo de modelo:Grupo de matriz 4:194554
194514 | Grupo de modelo:Grupo de matriz 4:194554
194517 | Grupo de modelo:Grupo de matriz 4:194554
194520 | Grupo de modelo:Grupo de matriz 4:194554
194523 | Grupo de modelo:Grupo de matriz 4:194554
194526 | Grupo de modelo:Grupo de matriz 4:194554
194529 | Grupo de modelo:Grupo de matriz 4:194554
194532 | Grupo de modelo:Grupo de matriz 4:194554
194535 | Grupo de modelo:Grupo de matriz 4:194554
194538 | Grupo de modelo:Grupo de matriz 4:194554
194541 | Grupo de modelo:Grupo de matriz 4:194554
194544 | Grupo de modelo:Grupo de matriz 4:194554
194547 | Grupo de modelo:Grupo de matriz 4:194554
194550 | Grupo de modelo:Grupo de matriz 4:194554
194553 | Grupo de modelo:Grupo de matriz 4:194554
194557 | Grupo de modelo:Grupo de matriz 4:194607
194560 | Grupo de modelo:Grupo de matriz 4:194607
194567 | Grupo de modelo:Grupo de matriz 4:194607
194570 | Grupo de modelo:Grupo de matriz 4:194607
194573 | Grupo de modelo:Grupo de matriz 4:194607
194576 | Grupo de modelo:Grupo de matriz 4:194607
194579 | Grupo de modelo:Grupo de matriz 4:194607
194582 | Grupo de modelo:Grupo de matriz 4:194607
194585 | Grupo de modelo:Grupo de matriz 4:194607
194588 | Grupo de modelo:Grupo de matriz 4:194607
194591 | Grupo de modelo:Grupo de matriz 4:194607
194594 | Grupo de modelo:Grupo de matriz 4:194607
194597 | Grupo de modelo:Grupo de matriz 4:194607
194600 | Grupo de modelo:Grupo de matriz 4:194607
194603 | Grupo de modelo:Grupo de matriz 4:194607
194606 | Grupo de modelo:Grupo de matriz 4:194607
194610 | Grupo de modelo:Grupo de matriz 4:194660
194613 | Grupo de modelo:Grupo de matriz 4:194660
194620 | Grupo de modelo:Grupo de matriz 4:194660
194623 | Grupo de modelo:Grupo de matriz 4:194660
194626 | Grupo de modelo:Grupo de matriz 4:194660
194629 | Grupo de modelo:Grupo de matriz 4:194660
194632 | Grupo de modelo:Grupo de matriz 4:194660
194635 | Grupo de modelo:Grupo de matriz 4:194660
194638 | Grupo de modelo:Grupo de matriz 4:194660
194641 | Grupo de modelo:Grupo de matriz 4:194660
194644 | Grupo de modelo:Grupo de matriz 4:194660
194647 | Grupo de modelo:Grupo de matriz 4:194660
194650 | Grupo de modelo:Grupo de matriz 4:194660
194653 | Grupo de modelo:Grupo de matriz 4:194660
194656 | Grupo de modelo:Grupo de matriz 4:194660
194659 | Grupo de modelo:Grupo de matriz 4:194660
194717 | Grupo de modelo:Grupo de matriz 4:194767
194720 | Grupo de modelo:Grupo de matriz 4:194767
194727 | Grupo de modelo:Grupo de matriz 4:194767
194730 | Grupo de modelo:Grupo de matriz 4:194767
194733 | Grupo de modelo:Grupo de matriz 4:194767
194736 | Grupo de modelo:Grupo de matriz 4:194767
194739 | Grupo de modelo:Grupo de matriz 4:194767
194742 | Grupo de modelo:Grupo de matriz 4:194767
194745 | Grupo de modelo:Grupo de matriz 4:194767
194748 | Grupo de modelo:Grupo de matriz 4:194767
194751 | Grupo de modelo:Grupo de matriz 4:194767
194754 | Grupo de modelo:Grupo de matriz 4:194767
194757 | Grupo de modelo:Grupo de matriz 4:194767
194760 | Grupo de modelo:Grupo de matriz 4:194767
194763 | Grupo de modelo:Grupo de matriz 4:194767
194766 | Grupo de modelo:Grupo de matriz 4:194767
194770 | Grupo de modelo:Grupo de matriz 4:194820
194773 | Grupo de modelo:Grupo de matriz 4:194820
194780 | Grupo de modelo:Grupo de matriz 4:194820
194783 | Grupo de modelo:Grupo de matriz 4:194820
194786 | Grupo de modelo:Grupo de matriz 4:194820
194789 | Grupo de modelo:Grupo de matriz 4:194820
194792 | Grupo de modelo:Grupo de matriz 4:194820
194795 | Grupo de modelo:Grupo de matriz 4:194820
194798 | Grupo de modelo:Grupo de matriz 4:194820
194801 | Grupo de modelo:Grupo de matriz 4:194820
194804 | Grupo de modelo:Grupo de matriz 4:194820
194807 | Grupo de modelo:Grupo de matriz 4:194820
194810 | Grupo de modelo:Grupo de matriz 4:194820
194813 | Grupo de modelo:Grupo de matriz 4:194820
194816 | Grupo de modelo:Grupo de matriz 4:194820
194819 | Grupo de modelo:Grupo de matriz 4:194820
194823 | Grupo de modelo:Grupo de matriz 4:194873
194826 | Grupo de modelo:Grupo de matriz 4:194873
194833 | Grupo de modelo:Grupo de matriz 4:194873
194836 | Grupo de modelo:Grupo de matriz 4:194873
194839 | Grupo de modelo:Grupo de matriz 4:194873
194842 | Grupo de modelo:Grupo de matriz 4:194873
194845 | Grupo de modelo:Grupo de matriz 4:194873
194848 | Grupo de modelo:Grupo de matriz 4:194873
194851 | Grupo de modelo:Grupo de matriz 4:194873
194854 | Grupo de modelo:Grupo de matriz 4:194873
194857 | Grupo de modelo:Grupo de matriz 4:194873
194860 | Grupo de modelo:Grupo de matriz 4:194873
194863 | Grupo de modelo:Grupo de matriz 4:194873
194866 | Grupo de modelo:Grupo de matriz 4:194873
194869 | Grupo de modelo:Grupo de matriz 4:194873
194872 | Grupo de modelo:Grupo de matriz 4:194873
194876 | Grupo de modelo:Grupo de matriz 4:194926
194879 | Grupo de modelo:Grupo de matriz 4:194926
194886 | Grupo de modelo:Grupo de matriz 4:194926
194889 | Grupo de modelo:Grupo de matriz 4:194926
194892 | Grupo de modelo:Grupo de matriz 4:194926
194895 | Grupo de modelo:Grupo de matriz 4:194926
194898 | Grupo de modelo:Grupo de matriz 4:194926
194901 | Grupo de modelo:Grupo de matriz 4:194926
194904 | Grupo de modelo:Grupo de matriz 4:194926
194907 | Grupo de modelo:Grupo de matriz 4:194926
194910 | Grupo de modelo:Grupo de matriz 4:194926
194913 | Grupo de modelo:Grupo de matriz 4:194926
194916 | Grupo de modelo:Grupo de matriz 4:194926
194919 | Grupo de modelo:Grupo de matriz 4:194926
194922 | Grupo de modelo:Grupo de matriz 4:194926
194925 | Grupo de modelo:Grupo de matriz 4:194926
194929 | Grupo de modelo:Grupo de matriz 4:194979
194932 | Grupo de modelo:Grupo de matriz 4:194979
194939 | Grupo de modelo:Grupo de matriz 4:194979
194942 | Grupo de modelo:Grupo de matriz 4:194979
194945 | Grupo de modelo:Grupo de matriz 4:194979
194948 | Grupo de modelo:Grupo de matriz 4:194979
194951 | Grupo de modelo:Grupo de matriz 4:194979
194954 | Grupo de modelo:Grupo de matriz 4:194979
194957 | Grupo de modelo:Grupo de matriz 4:194979
194960 | Grupo de modelo:Grupo de matriz 4:194979
194963 | Grupo de modelo:Grupo de matriz 4:194979
194966 | Grupo de modelo:Grupo de matriz 4:194979
194969 | Grupo de modelo:Grupo de matriz 4:194979
194972 | Grupo de modelo:Grupo de matriz 4:194979
194975 | Grupo de modelo:Grupo de matriz 4:194979
194978 | Grupo de modelo:Grupo de matriz 4:194979

# IfcGroup: Grupo de modelo:Grupo de matriz 4 (28)
Name (Grupo de modelo:Grupo de matriz 4:...) | Group
177664 | Grupo de modelo:STR- PERGOLA PATIS- 01:178950
177725 | Grupo de modelo:STR- PERGOLA PATIS- 01:178950
181588 | Grupo de modelo:STR- PERGOLA PATIS- 01:181963
181641 | Grupo de modelo:STR- PERGOLA PATIS- 01:181963
182070 | Grupo de modelo:STR- PERGOLA PATIS- 01:182445
182123 | Grupo de modelo:STR- PERGOLA PATIS- 01:182445
182552 | Grupo de modelo:STR- PERGOLA PATIS- 01:182927
182605 | Grupo de modelo:STR- PERGOLA PATIS- 01:182927
191019 | Grupo de modelo:STR- PERGOLA PATIS- 01:178950
191072 | Grupo de modelo:STR- PERGOLA PATIS- 01:178950
191125 | Grupo de modelo:STR- PERGOLA PATIS- 01:178950
191178 | Grupo de modelo:STR- PERGOLA PATIS- 01:178950
191231 | Grupo de modelo:STR- PERGOLA PATIS- 01:178950
194129 | Grupo de modelo:STR- PERGOLA PATIS- 01:181963
194182 | Grupo de modelo:STR- PERGOLA PATIS- 01:181963
194235 | Grupo de modelo:STR- PERGOLA PATIS- 01:181963
194288 | Grupo de modelo:STR- PERGOLA PATIS- 01:181963
194341 | Grupo de modelo:STR- PERGOLA PATIS- 01:181963
194448 | Grupo de modelo:STR- PERGOLA PATIS- 01:182445
194501 | Grupo de modelo:STR- PERGOLA PATIS- 01:182445
194554 | Grupo de modelo:STR- PERGOLA PATIS- 01:182445
194607 | Grupo de modelo:STR- PERGOLA PATIS- 01:182445
194660 | Grupo de modelo:STR- PERGOLA PATIS- 01:182445
194767 | Grupo de modelo:STR- PERGOLA PATIS- 01:182927
194820 | Grupo de modelo:STR- PERGOLA PATIS- 01:182927
194873 | Grupo de modelo:STR- PERGOLA PATIS- 01:182927
194926 | Grupo de modelo:STR- PERGOLA PATIS- 01:182927
194979 | Grupo de modelo:STR- PERGOLA PATIS- 01:182927

# IfcGroup: Grupo de modelo:Grupo de matriz 5 (64)
Name (Grupo de modelo:Grupo de matriz 5:...) | Group
187539 | Grupo de modelo:STR- PERGOLA PATIS- 01:178950
187544 | Grupo de modelo:STR- PERGOLA PATIS- 01:178950
187570 | Grupo de modelo:STR- PERGOLA PATIS- 01:178950
187574 | Grupo de modelo:STR- PERGOLA PATIS- 01:178950
187578 | Grupo de modelo:STR- PERGOLA PATIS- 01:178950
187582 | Grupo de modelo:STR- PERGOLA PATIS- 01:178950
187586 | Grupo de modelo:STR- PERGOLA PATIS- 01:178950
187590 | Grupo de modelo:STR- PERGOLA PATIS- 01:178950
187594 | Grupo de modelo:STR- PERGOLA PATIS- 01:178950
187598 | Grupo de modelo:STR- PERGOLA PATIS- 01:178950
187602 | Grupo de modelo:STR- PERGOLA PATIS- 01:178950
187606 | Grupo de modelo:STR- PERGOLA PATIS- 01:178950
187610 | Grupo de modelo:STR- PERGOLA PATIS- 01:178950
187614 | Grupo de modelo:STR- PERGOLA PATIS- 01:178950
187618 | Grupo de modelo:STR- PERGOLA PATIS- 01:178950
187679 | Grupo de modelo:STR- PERGOLA PATIS- 01:178950
194027 | Grupo de modelo:STR- PERGOLA PATIS- 01:181963
194030 | Grupo de modelo:STR- PERGOLA PATIS- 01:181963
194037 | Grupo de modelo:STR- PERGOLA PATIS- 01:181963
194040 | Grupo de modelo:STR- PERGOLA PATIS- 01:181963
194043 | Grupo de modelo:STR- PERGOLA PATIS- 01:181963
194046 | Grupo de modelo:STR- PERGOLA PATIS- 01:181963
194049 | Grupo de modelo:STR- PERGOLA PATIS- 01:181963
194052 | Grupo de modelo:STR- PERGOLA PATIS- 01:181963
194055 | Grupo de modelo:STR- PERGOLA PATIS- 01:181963
194058 | Grupo de modelo:STR- PERGOLA PATIS- 01:181963
194061 | Grupo de modelo:STR- PERGOLA PATIS- 01:181963
194064 | Grupo de modelo:STR- PERGOLA PATIS- 01:181963
194067 | Grupo de modelo:STR- PERGOLA PATIS- 01:181963
194070 | Grupo de modelo:STR- PERGOLA PATIS- 01:181963
194073 | Grupo de modelo:STR- PERGOLA PATIS- 01:181963
194076 | Grupo de modelo:STR- PERGOLA PATIS- 01:181963
194346 | Grupo de modelo:STR- PERGOLA PATIS- 01:182445
194349 | Grupo de modelo:STR- PERGOLA PATIS- 01:182445
194356 | Grupo de modelo:STR- PERGOLA PATIS- 01:182445
194359 | Grupo de modelo:STR- PERGOLA PATIS- 01:182445
194362 | Grupo de modelo:STR- PERGOLA PATIS- 01:182445
194365 | Grupo de modelo:STR- PERGOLA PATIS- 01:182445
194368 | Grupo de modelo:STR- PERGOLA PATIS- 01:182445
194371 | Grupo de modelo:STR- PERGOLA PATIS- 01:182445
194374 | Grupo de modelo:STR- PERGOLA PATIS- 01:182445
194377 | Grupo de modelo:STR- PERGOLA PATIS- 01:182445
194380 | Grupo de modelo:STR- PERGOLA PATIS- 01:182445
194383 | Grupo de modelo:STR- PERGOLA PATIS- 01:182445
194386 | Grupo de modelo:STR- PERGOLA PATIS- 01:182445
194389 | Grupo de modelo:STR- PERGOLA PATIS- 01:182445
194392 | Grupo de modelo:STR- PERGOLA PATIS- 01:182445
194395 | Grupo de modelo:STR- PERGOLA PATIS- 01:182445
194665 | Grupo de modelo:STR- PERGOLA PATIS- 01:182927
194668 | Grupo de modelo:STR- PERGOLA PATIS- 01:182927
194675 | Grupo de modelo:STR- PERGOLA PATIS- 01:182927
194678 | Grupo de modelo:STR- PERGOLA PATIS- 01:182927
194681 | Grupo de modelo:STR- PERGOLA PATIS- 01:182927
194684 | Grupo de modelo:STR- PERGOLA PATIS- 01:182927
194687 | Grupo de modelo:STR- PERGOLA PATIS- 01:182927
194690 | Grupo de modelo:STR- PERGOLA PATIS- 01:182927
194693 | Grupo de modelo:STR- PERGOLA PATIS- 01:182927
194696 | Grupo de modelo:STR- PERGOLA PATIS- 01:182927
194699 | Grupo de modelo:STR- PERGOLA PATIS- 01:182927
194702 | Grupo de modelo:STR- PERGOLA PATIS- 01:182927
194705 | Grupo de modelo:STR- PERGOLA PATIS- 01:182927
194708 | Grupo de modelo:STR- PERGOLA PATIS- 01:182927
194711 | Grupo de modelo:STR- PERGOLA PATIS- 01:182927
194714 | Grupo de modelo:STR- PERGOLA PATIS- 01:182927

# IfcGroup: Grupo de modelo:Grupo de matriz 6 (64)
Name (Grupo de modelo:Grupo de matriz 6:...) | Group
196769 | Grupo de modelo:STR- PERGOLA PATIS- 01:178950
196774 | Grupo de modelo:STR- PERGOLA PATIS- 01:178950
196790 | Grupo de modelo:STR- PERGOLA PATIS- 01:178950
196794 | Grupo de modelo:STR- PERGOLA PATIS- 01:178950
196798 | Grupo de modelo:STR- PERGOLA PATIS- 01:178950
196802 | Grupo de modelo:STR- PERGOLA PATIS- 01:178950
196806 | Grupo de modelo:STR- PERGOLA PATIS- 01:178950
196810 | Grupo de modelo:STR- PERGOLA PATIS- 01:178950
196814 | Grupo de modelo:STR- PERGOLA PATIS- 01:178950
196818 | Grupo de modelo:STR- PERGOLA PATIS- 01:178950
196822 | Grupo de modelo:STR- PERGOLA PATIS- 01:178950
196826 | Grupo de modelo:STR- PERGOLA PATIS- 01:178950
196830 | Grupo de modelo:STR- PERGOLA PATIS- 01:178950
196834 | Grupo de modelo:STR- PERGOLA PATIS- 01:178950
196838 | Grupo de modelo:STR- PERGOLA PATIS- 01:178950
196898 | Grupo de modelo:STR- PERGOLA PATIS- 01:178950
197243 | Grupo de modelo:STR- PERGOLA PATIS- 01:181963
197246 | Grupo de modelo:STR- PERGOLA PATIS- 01:181963
197253 | Grupo de modelo:STR- PERGOLA PATIS- 01:181963
197256 | Grupo de modelo:STR- PERGOLA PATIS- 01:181963
197259 | Grupo de modelo:STR- PERGOLA PATIS- 01:181963
197262 | Grupo de modelo:STR- PERGOLA PATIS- 01:181963
197265 | Grupo de modelo:STR- PERGOLA PATIS- 01:181963
197268 | Grupo de modelo:STR- PERGOLA PATIS- 01:181963
197271 | Grupo de modelo:STR- PERGOLA PATIS- 01:181963
197274 | Grupo de modelo:STR- PERGOLA PATIS- 01:181963
197277 | Grupo de modelo:STR- PERGOLA PATIS- 01:181963
197280 | Grupo de modelo:STR- PERGOLA PATIS- 01:181963
197283 | Grupo de modelo:STR- PERGOLA PATIS- 01:181963
197286 | Grupo de modelo:STR- PERGOLA PATIS- 01:181963
197289 | Grupo de modelo:STR- PERGOLA PATIS- 01:181963
197292 | Grupo de modelo:STR- PERGOLA PATIS- 01:181963
197297 | Grupo de modelo:STR- PERGOLA PATIS- 01:182445
197300 | Grupo de modelo:STR- PERGOLA PATIS- 01:182445
197307 | Grupo de modelo:STR- PERGOLA PATIS- 01:182445
197310 | Grupo de modelo:STR- PERGOLA PATIS- 01:182445
197313 | Grupo de modelo:STR- PERGOLA PATIS- 01:182445
197316 | Grupo de modelo:STR- PERGOLA PATIS- 01:182445
197319 | Grupo de modelo:STR- PERGOLA PATIS- 01:182445
197322 | Grupo de modelo:STR- PERGOLA PATIS- 01:182445
197325 | Grupo de modelo:STR- PERGOLA PATIS- 01:182445
197328 | Grupo de modelo:STR- PERGOLA PATIS- 01:182445
197331 | Grupo de modelo:STR- PERGOLA PATIS- 01:182445
197334 | Grupo de modelo:STR- PERGOLA PATIS- 01:182445
197337 | Grupo de modelo:STR- PERGOLA PATIS- 01:182445
197340 | Grupo de modelo:STR- PERGOLA PATIS- 01:182445
197343 | Grupo de modelo:STR- PERGOLA PATIS- 01:182445
197346 | Grupo de modelo:STR- PERGOLA PATIS- 01:182445
197351 | Grupo de modelo:STR- PERGOLA PATIS- 01:182927
197354 | Grupo de modelo:STR- PERGOLA PATIS- 01:182927
197361 | Grupo de modelo:STR- PERGOLA PATIS- 01:182927
197364 | Grupo de modelo:STR- PERGOLA PATIS- 01:182927
197367 | Grupo de modelo:STR- PERGOLA PATIS- 01:182927
197370 | Grupo de modelo:STR- PERGOLA PATIS- 01:182927
197373 | Grupo de modelo:STR- PERGOLA PATIS- 01:182927
197376 | Grupo de modelo:STR- PERGOLA PATIS- 01:182927
197379 | Grupo de modelo:STR- PERGOLA PATIS- 01:182927
197382 | Grupo de modelo:STR- PERGOLA PATIS- 01:182927
197385 | Grupo de modelo:STR- PERGOLA PATIS- 01:182927
197388 | Grupo de modelo:STR- PERGOLA PATIS- 01:182927
197391 | Grupo de modelo:STR- PERGOLA PATIS- 01:182927
197394 | Grupo de modelo:STR- PERGOLA PATIS- 01:182927
197397 | Grupo de modelo:STR- PERGOLA PATIS- 01:182927
197400 | Grupo de modelo:STR- PERGOLA PATIS- 01:182927

# IfcGroup: Grupo de modelo:Mp-6 2, Grupo de modelo:Mp-6 2:42619
Group: Grupo de modelo:Murs urbanització 2:43208

# IfcGroup: Grupo de modelo:RP- mP6 2, Grupo de modelo:RP- mP6 2:42608
Group: Grupo de modelo:Murs urbanització 2:43208

# IfcGroup: Grupo de modelo:STR- PERGOLA PATIS- 01 (4)
Name (Grupo de modelo:STR- PERGOLA PATIS- 01:...) | Group
178950 | Grupo de modelo:STR- Pergola pati infantil:84747
181963 | Grupo de modelo:STR- Pergola pati infantil:84624
182445 | Grupo de modelo:STR- Pergola pati infantil:84665
182927 | Grupo de modelo:STR- Pergola pati infantil:84706

# IfcGroup: Grupo de modelo:pergola (7)
Group: Grupo de modelo:Conjunt Pergola pati infantil:42531
Name (Grupo de modelo:pergola:...)
42530
42536
42541
42546
42551
42556
42561

# IfcOpeningElement: Opening (37)
Name | In | Reference | sets with these values
2 x Suelo:STR- L- Formigó- Alveloar- T1- 25 cm:41149:2 | PC- Coberta STR | STR- L- Formigó- Alveloar- T1- 25 cm | 2
Suelo:STR- L- Formigó- Alveloar- T1- 25 cm:41149:3 | PC- Coberta STR | STR- L- Formigó- Alveloar- T1- 25 cm | 2
Suelo:STR- L- Formigó- Alveloar- T1- 25 cm:41149:4 | PC- Coberta STR | STR- L- Formigó- Alveloar- T1- 25 cm | 2
6 x Suelo:STR- L- Formigó- Llosa- T1- 32 cm:43711 | P0- Escola | STR- L- Formigó- Llosa- T1- 32 cm | 2
4 x Muro básico:STR- M- Formigó- Genèric- T1- 30 cm:43652 | PS1- Gimnàs | STR- M- Formigó- Genèric- T1- 30 cm | 2
Suelo:STR- L- Formigó- Solera- T1- 15 cm:43657 | PS1- Vestuari | STR- L- Formigó- Solera- T1- 15 cm | 2 | Group: Grupo de modelo:STR- conjunt soleres:41868
3 x Suelo:STR- L- Formigó- Alveloar- T1- 25 cm:41647:2 | PC- Coberta STR | STR- L- Formigó- Alveloar- T1- 25 cm | 2
Suelo:STR- L- Formigó- Alveloar- T1- 25 cm:41647:3 | PC- Coberta STR | STR- L- Formigó- Alveloar- T1- 25 cm | 2
Muro básico:STR- M- Formigó- Genèric- T1- 35 cm:41877 | PS1- Gimnàs | STR- Pas installacions | 2
Muro básico:STR- M- Formigó- Genèric- T1- 20 cm:43650 | PS1- Vestuari | STR- M- Formigó- Genèric- T1- 20 cm | 2
Muro básico:STR- M- Formigó- Genèric- T1- 35 cm:42351 | PS1- Vestuari | STR- Pas installacions | 2
2 x Muro básico:STR- M- Formigó- Genèric- T1- 30 cm:43652 | P0- Escola | STR- M- Formigó- Genèric- T1- 30 cm | 2 | Group: Grupo de modelo:Murs urbanització 2:43208
Muro básico:STR- M- Bloc Formigó- T1- 15 cm:198168:1 | PS1- Vestuari | STR- M- Bloc Formigó- T1- 15 cm | 2
Muro básico:STR- M- Bloc Formigó- T1- 15 cm:198168:2 | PS1- Vestuari | STR- M- Bloc Formigó- T1- 15 cm | 2
Muro básico:STR- M- Bloc Formigó- T1- 15 cm:198231:1 | PS1- Vestuari | STR- M- Bloc Formigó- T1- 15 cm | 2
Muro básico:STR- M- Bloc Formigó- T1- 15 cm:198231:2 | PS1- Vestuari | STR- M- Bloc Formigó- T1- 15 cm | 2
Muro básico:STR- M- Bloc Formigó- T1- 15 cm:198289:1 | PS1- Vestuari | STR- M- Bloc Formigó- T1- 15 cm | 2
Muro básico:STR- M- Bloc Formigó- T1- 15 cm:198289:2 | PS1- Vestuari | STR- M- Bloc Formigó- T1- 15 cm | 2
Muro básico:STR- M- Formigó- Genèric- T1- 40 cm:41498 | PS1- Gimnàs
Muro básico:STR- M- Formigó- Genèric- T1- 40 cm:41499 | PS1- Vestuari
Muro básico:STR- M- Formigó- Genèric- T1- 40 cm:41774 | PS1- Vestuari
Muro básico:STR- M- Formigó- Genèric- T1- 40 cm:41780 | PS1- Vestuari
Muro básico:STR- M- Formigó- Genèric- T1- 40 cm:41786 | PS1- Vestuari
Muro básico:STR- M- Formigó- Genèric- T1- 40 cm:41792 | PS1- Vestuari
Muro básico:STR- M- Formigó- Genèric- T1- 40 cm:42019 | PS1- Gimnàs

# IfcSlab: Descansillo monolítico:STR- Repla acer (3)
In: PS1- Vestuari
Type - PredefinedType: LANDING
Type - Pset_SlabCommon - IsExternal: no
Material: _PAV escales STR, _Acer- STR
Pset_QuantityTakeOff - Reference: STR- Repla acer; sets with these values: 2
Pset_SlabCommon - PitchAngle: 0 deg; Reference: STR- Repla acer
Name (Escalera moldeada in situ:Escalera:...)
43273 Landing 1
43273 Landing 2
92117 Landing 1

# IfcSlab: Descansillo monolítico:STR- Repla formigó 15cm (4)
Type - PredefinedType: LANDING
Type - Pset_SlabCommon - IsExternal: no
Material: _Formigó- T1- STR
Pset_QuantityTakeOff - Reference: STR- Repla formigó 15cm; sets with these values: 2
Pset_SlabCommon - PitchAngle: 0 deg; Reference: STR- Repla formigó 15cm
Name (Escalera moldeada in situ:Escalera:...) | In
41321 Landing 1 | PS1- Gimnàs
41333 Landing 1 | PS1- Gimnàs
42180 Landing 1 | PS1- Vestuari
42290 Landing 1 | PS1- Vestuari

# IfcSlab: STR- Connexió sabat mur biblio1:STR- Connexió sabat mur biblio, STR- Connexió sabat mur biblio1:STR- Connexió sabat mur biblio:42307
In: PS1- Gimnàs
Type - PredefinedType: BASESLAB; Material: _Formigó- T1- STR
Type - Pset_SlabCommon - IsExternal: no
Pset_QuantityTakeOff - Reference: STR- Connexió sabat mur biblio; sets with these values: 2
Pset_SlabCommon - Reference: STR- Connexió sabat mur biblio

# IfcSlab: STR- Connexió sabat mur biblio2:STR- Connexió sabat mur biblio, STR- Connexió sabat mur biblio2:STR- Connexió sabat mur biblio:156901
In: PS1- Vestuari
Type - PredefinedType: BASESLAB; Material: _Formigó- T1- STR
Type - Pset_SlabCommon - IsExternal: no
Pset_QuantityTakeOff - Reference: STR- Connexió sabat mur biblio; sets with these values: 2
Pset_SlabCommon - Reference: STR- Connexió sabat mur biblio

# IfcSlab: STR- Connexió sabat mur biblio3:STR- Connexió sabat mur biblio, STR- Connexió sabat mur biblio3:STR- Connexió sabat mur biblio:156980
In: PS1- Vestuari
Type - PredefinedType: BASESLAB; Material: _Formigó- T1- STR
Type - Pset_SlabCommon - IsExternal: no
Pset_QuantityTakeOff - Reference: STR- Connexió sabat mur biblio; sets with these values: 2
Pset_SlabCommon - Reference: STR- Connexió sabat mur biblio

# IfcSlab: STR- Connexió sabat mur biblio:STR- Connexió sabat mur biblio, STR- Connexió sabat mur biblio:STR- Connexió sabat mur biblio:42215
In: PS1- Gimnàs
Type - PredefinedType: BASESLAB; Material: _Formigó- T1- STR
Type - Pset_SlabCommon - IsExternal: no
Pset_QuantityTakeOff - Reference: STR- Connexió sabat mur biblio; sets with these values: 2
Pset_SlabCommon - Reference: STR- Connexió sabat mur biblio

# IfcSlab: STR- S- Formigó- Fosat ascensor:STR- S- Formigó- Fosat ascensor, STR- S- Formigó- Fosat ascensor:STR- S- Formigó- Fosat ascensor:41911
In: PS1- Gimnàs
Type - PredefinedType: BASESLAB; Material: _Formigó Pobre- T1- STR
Type - Pset_SlabCommon - IsExternal: no
Pset_QuantityTakeOff - Reference: STR- S- Formigó- Fosat ascensor; sets with these values: 2
Pset_SlabCommon - Reference: STR- S- Formigó- Fosat ascensor

# IfcSlab: STR- S- Formigó- H1:STR- S- Formigó- H1, STR- S- Formigó- H1:STR- S- Formigó- H1:41980
In: PS1- Gimnàs
Type - PredefinedType: BASESLAB; Material: _Formigó- T1- STR
Type - Pset_SlabCommon - IsExternal: no
Pset_QuantityTakeOff - Reference: STR- S- Formigó- H1; sets with these values: 2
Pset_SlabCommon - Reference: STR- S- Formigó- H1

# IfcSlab: STR- S- Formigó- Ma urb:STR- S- Formigó- Ma urb, STR- S- Formigó- Ma urb:STR- S- Formigó- Ma urb:42001
In: PS1- Gimnàs
Type - PredefinedType: BASESLAB; Material: _Formigó- T1- STR
Type - Pset_SlabCommon - IsExternal: no
Pset_QuantityTakeOff - Reference: STR- S- Formigó- Ma urb; sets with these values: 2
Pset_SlabCommon - Reference: STR- S- Formigó- Ma urb

# IfcSlab: STR- S- Formigó- Mp2:STR- S- Formigó- Mp4, STR- S- Formigó- Mp2:STR- S- Formigó- Mp4:42852
In: PS1- Gimnàs
Type - PredefinedType: BASESLAB; Material: _Formigó- T1- STR
Type - Pset_SlabCommon - IsExternal: no
Pset_QuantityTakeOff - Reference: STR- S- Formigó- Mp4; sets with these values: 2
Pset_SlabCommon - Reference: STR- S- Formigó- Mp4
Group: Grupo de modelo:Murs urbanització 2:43208

# IfcSlab: STR- S- Formigó- Rectangular+pou- T1:100x160x60 cm (8)
In: P0- Escola
Type - PredefinedType: BASESLAB; Material: _Formigó- T1- STR
Type - Pset_SlabCommon - IsExternal: no
Pset_QuantityTakeOff - Reference: 100x160x60 cm; sets with these values: 2
Pset_SlabCommon - Reference: 100x160x60 cm
Name (STR- S- Formigó- Rectangular+pou- T1:100x160x60 cm:...)
41743
41745
41747
41749
41751
41753
41755
41757

# IfcSlab: STR- S- Formigó- Rectangular+pou- T1:130x200x60 cm (2)
In: PS1- Vestuari
Type - PredefinedType: BASESLAB; Material: _Formigó- T1- STR
Type - Pset_SlabCommon - IsExternal: no
Pset_QuantityTakeOff - Reference: 130x200x60 cm; sets with these values: 2
Pset_SlabCommon - Reference: 130x200x60 cm
Name (STR- S- Formigó- Rectangular+pou- T1:130x200x60 cm:...)
41922
41924

# IfcSlab: STR- S- Formigó- Rectangular- T1:100x100x60 cm, STR- S- Formigó- Rectangular- T1:100x100x60 cm:41848
In: PS1- Gimnàs
Type - PredefinedType: BASESLAB; Material: _Formigó- T1- STR
Type - Pset_SlabCommon - IsExternal: no
Pset_QuantityTakeOff - Reference: 100x100x60 cm; sets with these values: 2
Pset_SlabCommon - PitchAngle: 0 deg; Reference: 100x100x60 cm

# IfcSlab: STR- S- Formigó- Rectangular- T1:100x140x60 cm (8)
In: P0- Escola
Type - PredefinedType: BASESLAB; Material: _Formigó- T1- STR
Type - Pset_SlabCommon - IsExternal: no
Pset_QuantityTakeOff - Reference: 100x140x60 cm; sets with these values: 2
Pset_SlabCommon - Reference: 100x140x60 cm
Name (STR- S- Formigó- Rectangular- T1:100x140x60 cm:...)
41713
41715
41717
41719
41721
41723
41725
41759

# IfcSlab: STR- S- Formigó- Rectangular- T1:100x160x60 cm (8)
In: P0- Escola
Type - PredefinedType: BASESLAB; Material: _Formigó- T1- STR
Type - Pset_SlabCommon - IsExternal: no
Pset_QuantityTakeOff - Reference: 100x160x60 cm; sets with these values: 2
Pset_SlabCommon - PitchAngle: 0 deg; Reference: 100x160x60 cm
Name (STR- S- Formigó- Rectangular- T1:100x160x60 cm:...)
41727
41729
41731
41733
41735
41737
41739
41741

# IfcSlab: STR- S- Formigó- Rectangular- T1:140x200x60 cm (5)
In: PS1- Gimnàs
Type - PredefinedType: BASESLAB; Material: _Formigó- T1- STR
Type - Pset_SlabCommon - IsExternal: no
Pset_QuantityTakeOff - Reference: 140x200x60 cm; sets with these values: 2
Pset_SlabCommon - PitchAngle: 0 deg; Reference: 140x200x60 cm
Name (STR- S- Formigó- Rectangular- T1:140x200x60 cm:...)
41850
41852
41854
41858
41885

# IfcSlab: STR- S- Formigó- Rectangular- T1:140x250x60 cm (7)
Type - PredefinedType: BASESLAB; Material: _Formigó- T1- STR
Type - Pset_SlabCommon - IsExternal: no
Pset_QuantityTakeOff - Reference: 140x250x60 cm; sets with these values: 2
Pset_SlabCommon - Reference: 140x250x60 cm
Name (STR- S- Formigó- Rectangular- T1:140x250x60 cm:...) | In
41822 | PS1- Vestuari
41824 | PS1- Vestuari | Pset_SlabCommon - PitchAngle: 0 deg
41826 | PS1- Vestuari
41828 | PS1- Vestuari
41875 | PS1- Gimnàs
41881 | PS1- Gimnàs
41883 | PS1- Gimnàs

# IfcSlab: STR- S- Formigó- Rectangular- T1:160x300x60 cm, STR- S- Formigó- Rectangular- T1:160x300x60 cm:41895
In: PS1- Gimnàs
Type - PredefinedType: BASESLAB; Material: _Formigó- T1- STR
Type - Pset_SlabCommon - IsExternal: no
Pset_QuantityTakeOff - Reference: 160x300x60 cm; sets with these values: 2
Pset_SlabCommon - Reference: 160x300x60 cm

# IfcSlab: STR- S- Formigó- Rectangular- T1:180x220x60 cm, STR- S- Formigó- Rectangular- T1:180x220x60 cm:41856
In: PS1- Gimnàs
Type - PredefinedType: BASESLAB; Material: _Formigó- T1- STR
Type - Pset_SlabCommon - IsExternal: no
Pset_QuantityTakeOff - Reference: 180x220x60 cm; sets with these values: 2
Pset_SlabCommon - PitchAngle: 0 deg; Reference: 180x220x60 cm

# IfcSlab: STR- S- Fromigó- Sabata eix 13:STR- S- Fromigó- Sabata eix 13, STR- S- Fromigó- Sabata eix 13:STR- S- Fromigó- Sabata eix 13:41804
In: PS1- Gimnàs
Type - PredefinedType: BASESLAB; Material: _Formigó Pobre- T1- STR
Type - Pset_SlabCommon - IsExternal: no
Pset_QuantityTakeOff - Reference: STR- S- Fromigó- Sabata eix 13; sets with these values: 2
Pset_SlabCommon - Reference: STR- S- Fromigó- Sabata eix 13

# IfcSlab: STR- S- formigó- Mp1:STR- S- formigó- Mp7, STR- S- formigó- Mp1:STR- S- formigó- Mp7:42710
In: PS1- Vestuari
Type - PredefinedType: BASESLAB; Material: _Formigó- T1- STR
Type - Pset_SlabCommon - IsExternal: no
Pset_QuantityTakeOff - Reference: STR- S- formigó- Mp7; sets with these values: 2
Pset_SlabCommon - Reference: STR- S- formigó- Mp7
Group: Grupo de modelo:Mp-6 2:42619

# IfcSlab: STR- Sabata- Unio sabata MP1:STR- Sabata- Unio sabata MP1, STR- Sabata- Unio sabata MP1:STR- Sabata- Unio sabata MP1:43159
In: PS1- Vestuari
Type - PredefinedType: BASESLAB; Material: _Formigó- T1- STR
Type - Pset_SlabCommon - IsExternal: no
Pset_QuantityTakeOff - Reference: STR- Sabata- Unio sabata MP1; sets with these values: 2
Pset_SlabCommon - Reference: STR- Sabata- Unio sabata MP1
Group: Grupo de modelo:Murs urbanització 2:43208

# IfcSlab: STR- Sabata- Unio sabata MP2:STR- Sabata- Unio sabata MP1, STR- Sabata- Unio sabata MP2:STR- Sabata- Unio sabata MP1:43169
In: PS1- Gimnàs
Type - PredefinedType: BASESLAB; Material: _Formigó- T1- STR
Type - Pset_SlabCommon - IsExternal: no
Pset_QuantityTakeOff - Reference: STR- Sabata- Unio sabata MP1; sets with these values: 2
Pset_SlabCommon - Reference: STR- Sabata- Unio sabata MP1
Group: Grupo de modelo:Murs urbanització 2:43208

# IfcSlab: STR- Sabata- Unio sabata MP3:STR- Sabata- Unio sabata MP1, STR- Sabata- Unio sabata MP3:STR- Sabata- Unio sabata MP1:43177
In: PS1- Gimnàs
Type - PredefinedType: BASESLAB; Material: _Formigó- T1- STR
Type - Pset_SlabCommon - IsExternal: no
Pset_QuantityTakeOff - Reference: STR- Sabata- Unio sabata MP1; sets with these values: 2
Pset_SlabCommon - Reference: STR- Sabata- Unio sabata MP1
Group: Grupo de modelo:Murs urbanització 2:43208

# IfcSlab: STR- Sabata- Unio sabata MP4:STR- Sabata- Unio sabata MP1, STR- Sabata- Unio sabata MP4:STR- Sabata- Unio sabata MP1:43185
In: PS1- Gimnàs
Type - PredefinedType: BASESLAB; Material: _Formigó- T1- STR
Type - Pset_SlabCommon - IsExternal: no
Pset_QuantityTakeOff - Reference: STR- Sabata- Unio sabata MP1; sets with these values: 2
Pset_SlabCommon - Reference: STR- Sabata- Unio sabata MP1
Group: Grupo de modelo:Murs urbanització 2:43208

# IfcSlab: STR- Sabata- Unio sabata MP5:STR- Sabata- Unio sabata MP1, STR- Sabata- Unio sabata MP5:STR- Sabata- Unio sabata MP1:43197
In: PS1- Gimnàs
Type - PredefinedType: BASESLAB; Material: _Formigó- T1- STR
Type - Pset_SlabCommon - IsExternal: no
Pset_QuantityTakeOff - Reference: STR- Sabata- Unio sabata MP1; sets with these values: 2
Pset_SlabCommon - Reference: STR- Sabata- Unio sabata MP1
Group: Grupo de modelo:Murs urbanització 2:43208

# IfcSlab: Suelo:STR- L- Formigó- Alveloar- T1- 25 cm (7)
In: PC- Coberta STR
Type - PredefinedType: FLOOR; Material: _Formigó- T1- STR 0.25 m
Type - Pset_SlabCommon - IsExternal: no
Pset_QuantityTakeOff - Reference: STR- L- Formigó- Alveloar- T1- 25 cm; sets with these values: 2
Pset_SlabCommon - LoadBearing: yes; Reference: STR- L- Formigó- Alveloar- T1- 25 cm; PitchAngle: 0 deg
Name (Suelo:STR- L- Formigó- Alveloar- T1- 25 cm:...)
41149
41149:2
41197
41359
41647
41647:2
41647:3

# IfcSlab: Suelo:STR- L- Formigó- Llosa- T1- 24 cm, Suelo:STR- L- Formigó- Llosa- T1- 24 cm:41416
In: P0- Escola
Pset_QuantityTakeOff - Reference: STR- L- Formigó- Llosa- T1- 24 cm; sets with these values: 2
Pset_SlabCommon - IsExternal: no; LoadBearing: yes; Reference: STR- L- Formigó- Llosa- T1- 24 cm; PitchAngle: 7.65231 deg

# IfcSlab: Suelo:STR- L- Formigó- Llosa- T1- 24 cm (4)
In: P0- Escola
Type - PredefinedType: FLOOR; Material: _Formigó- T1- STR 0.24 m
Type - Pset_SlabCommon - IsExternal: no
Pset_QuantityTakeOff - Reference: STR- L- Formigó- Llosa- T1- 24 cm; sets with these values: 2
Pset_SlabCommon - LoadBearing: yes; Reference: STR- L- Formigó- Llosa- T1- 24 cm
Name (Suelo:STR- L- Formigó- Llosa- T1- 24 cm:...) | PitchAngle (deg)
41169 | 0
41178 | 0
2 x 41416 | 7.65231

# IfcSlab: Suelo:STR- L- Formigó- Llosa- T1- 25 cm (6)
In: PC- Coberta STR
Type - PredefinedType: FLOOR; Material: _Formigó- T1- STR 0.25 m
Type - Pset_SlabCommon - IsExternal: no
Pset_QuantityTakeOff - Reference: STR- L- Formigó- Llosa- T1- 25 cm; sets with these values: 2
Pset_SlabCommon - PitchAngle: 0 deg; Reference: STR- L- Formigó- Llosa- T1- 25 cm
Name (Suelo:STR- L- Formigó- Llosa- T1- 25 cm:...) | LoadBearing
41209 | no
41368 | yes
41664 | no
41664:2 | no
41664:3 | no
200319 | no

# IfcSlab: Suelo:STR- L- Formigó- Llosa- T1- 30 cm, Suelo:STR- L- Formigó- Llosa- T1- 30 cm:89823
In: PC- Coberta STR
Type - PredefinedType: FLOOR; Material: _Formigó- T1- STR 0.3 m
Type - Pset_SlabCommon - IsExternal: no
Pset_QuantityTakeOff - Reference: STR- L- Formigó- Llosa- T1- 30 cm; sets with these values: 2
Pset_SlabCommon - LoadBearing: yes; PitchAngle: 0 deg; Reference: STR- L- Formigó- Llosa- T1- 30 cm

# IfcSlab: Suelo:STR- L- Formigó- Llosa- T1- 32 cm (3)
In: P0- Escola
Type - PredefinedType: FLOOR; Material: _Formigó- T1- STR 0.32 m
Type - Pset_SlabCommon - IsExternal: no
Pset_QuantityTakeOff - Reference: STR- L- Formigó- Llosa- T1- 32 cm; sets with these values: 2
Pset_SlabCommon - LoadBearing: yes; PitchAngle: 0 deg; Reference: STR- L- Formigó- Llosa- T1- 32 cm
Name (Suelo:STR- L- Formigó- Llosa- T1- 32 cm:...)
41154
41346
41635

# IfcSlab: Suelo:STR- L- Formigó- Solera exterior- T1- 15 cm (2)
In: PS1- Vestuari
Pset_QuantityTakeOff - Reference: STR- L- Formigó- Solera exterior- T1- 15 cm; sets with these values: 2
Pset_SlabCommon - IsExternal: no; LoadBearing: yes; Reference: STR- L- Formigó- Solera exterior- T1- 15 cm
Group: Grupo de modelo:STR- conjunt soleres:41868
Name (Suelo:STR- L- Formigó- Solera exterior- T1- 15 cm:...) | PitchAngle (deg)
41454 | 4.57392
41491 | 1.14576

# IfcSlab: Suelo:STR- L- Formigó- Solera exterior- T1- 15 cm (8)
Type - PredefinedType: FLOOR; Material: _Formigó- Solera- T1 ext- STR 0.15 m
Type - Pset_SlabCommon - IsExternal: no
Pset_QuantityTakeOff - Reference: STR- L- Formigó- Solera exterior- T1- 15 cm; sets with these values: 2
Pset_SlabCommon - LoadBearing: yes; Reference: STR- L- Formigó- Solera exterior- T1- 15 cm
Group: Grupo de modelo:STR- conjunt soleres:41868
Name (Suelo:STR- L- Formigó- Solera exterior- T1- 15 cm:...) | In | PitchAngle (deg)
41256 | PS1- Gimnàs | 0.904595
41264 | PS1- Vestuari | 1.22321
41446 | PS1- Gimnàs | 0
41454 | PS1- Vestuari | 4.57392
41454 | PS1- Vestuari | 4.57361
41454 | PS1- Vestuari | 0.859372
41491 | PS1- Vestuari | 1.14576
41491 | PS1- Vestuari | 0.984038

# IfcSlab: Suelo:STR- L- Formigó- Solera exterior- T1- 20 cm 2, Suelo:STR- L- Formigó- Solera exterior- T1- 20 cm 2:41570
In: P0- Escola
Type - PredefinedType: FLOOR
Type - Pset_SlabCommon - IsExternal: no
Material: _Formigó- Solera- T1 ext- STR; Group: Grupo de modelo:STR- Solera pati:41579
Pset_QuantityTakeOff - Reference: STR- L- Formigó- Solera exterior- T1- 20 cm 2; sets with these values: 2
Pset_SlabCommon - LoadBearing: yes; Reference: STR- L- Formigó- Solera exterior- T1- 20 cm 2; PitchAngle: 1.08092 deg

# IfcSlab: Suelo:STR- L- Formigó- Solera- T1- 15 cm, Suelo:STR- L- Formigó- Solera- T1- 15 cm:42267
In: PS1- Vestuari
Pset_QuantityTakeOff - Reference: STR- L- Formigó- Solera- T1- 15 cm; sets with these values: 2
Pset_SlabCommon - IsExternal: no; LoadBearing: yes; Reference: STR- L- Formigó- Solera- T1- 15 cm; PitchAngle: 2.75808 deg

# IfcSlab: Suelo:STR- L- Formigó- Solera- T1- 15 cm (9)
Type - PredefinedType: FLOOR; Material: _Formigó- Solera- T1- STR 0.15 m
Type - Pset_SlabCommon - IsExternal: no
Pset_QuantityTakeOff - Reference: STR- L- Formigó- Solera- T1- 15 cm; sets with these values: 2
Pset_SlabCommon - LoadBearing: yes; Reference: STR- L- Formigó- Solera- T1- 15 cm
Name (Suelo:STR- L- Formigó- Solera- T1- 15 cm:...) | In | PitchAngle (deg)
41229 | PS1- Gimnàs | 0 | Group: Grupo de modelo:STR- conjunt soleres:41868
41248 | PS1- Vestuari | 0 | Group: Grupo de modelo:STR- conjunt soleres:41868
41505 | PS1- Vestuari | 1.14576 | Group: Grupo de modelo:STR- conjunt soleres:41868
41945 | PS1- Vestuari | 1.14576
41954 | PS1- Vestuari | 0.763898
42149 | PS1- Vestuari | 0.954841
42267 | PS1- Vestuari | 2.75808
42267 | PS1- Vestuari | 13.1263
42267 | PS1- Vestuari | 3.9758

# IfcSlab: Suelo:STR- L- Formigó- Solera- T1- 20 cm (6)
Type - PredefinedType: FLOOR; Material: _Formigó- Solera- T1- STR 0.2 m
Type - Pset_SlabCommon - IsExternal: no
Pset_QuantityTakeOff - Reference: STR- L- Formigó- Solera- T1- 20 cm; sets with these values: 2
Pset_SlabCommon - LoadBearing: yes; PitchAngle: 0 deg; Reference: STR- L- Formigó- Solera- T1- 20 cm
Name (Suelo:STR- L- Formigó- Solera- T1- 20 cm:...) | In | Group
41284 | P0- Escola | Grupo de modelo:STR- Solera interior:42497
41292 | P0- Escola | Grupo de modelo:STR- Solera interior:42497
41532 | P0- Escola | Grupo de modelo:STR- Solera interior:42497
41545 | P0- Escola | Grupo de modelo:STR- Solera interior:42497
41558 | P0- Escola | Grupo de modelo:STR- Solera interior:42497
42239 | PS1- Vestuari

# IfcSlab: Suelo:STR- L- Formigó- Solera- T1- 24 cm, Suelo:STR- L- Formigó- Solera- T1- 24 cm:42440
In: P0- Escola
Type - PredefinedType: FLOOR; Material: _Formigó- Solera- T1- STR 0.24 m
Type - Pset_SlabCommon - IsExternal: no
Pset_QuantityTakeOff - Reference: STR- L- Formigó- Solera- T1- 24 cm; sets with these values: 2
Pset_SlabCommon - LoadBearing: yes; PitchAngle: 0 deg; Reference: STR- L- Formigó- Solera- T1- 24 cm
Group: Grupo de modelo:STR- Solera interior:42497

# IfcSlab: Suelo:STR- L- Formigó- Solera- T1- 32 cm (5)
In: P0- Escola
Type - PredefinedType: FLOOR; Material: _Formigó- Solera- T1- STR 0.32 m
Type - Pset_SlabCommon - IsExternal: no
Pset_QuantityTakeOff - Reference: STR- L- Formigó- Solera- T1- 32 cm; sets with these values: 2
Pset_SlabCommon - LoadBearing: yes; PitchAngle: 0 deg; Reference: STR- L- Formigó- Solera- T1- 32 cm
Group: Grupo de modelo:STR- Solera interior:42497
Name (Suelo:STR- L- Formigó- Solera- T1- 32 cm:...)
42452
42461
42470
42479
42488

# IfcStair: Escalera moldeada in situ:E-A1, Escalera moldeada in situ:Escalera:43273
In: PS1- Vestuari
Pset_QuantityTakeOff - Reference: E-A1
Pset_StairCommon - IsExternal: yes; Reference: E-A1; NumberOfRiser: 28; NumberOfTreads: 27; RiserHeight: 0.16 m; TreadLength: 0.3 m

# IfcStair: Escalera moldeada in situ:E-A2, Escalera moldeada in situ:Escalera:92117
In: PS1- Vestuari
ShapeType: STRAIGHT_RUN_STAIR
Pset_QuantityTakeOff - Reference: E-A2
Pset_StairCommon - IsExternal: yes; Reference: E-A2; NumberOfRiser: 10; NumberOfTreads: 10; RiserHeight: 0.176 m; TreadLength: 0.3 m

# IfcStair: Escalera moldeada in situ:E-X1- Exterior (6)
ShapeType: STRAIGHT_RUN_STAIR
Pset_QuantityTakeOff - Reference: E-X1- Exterior
Pset_StairCommon - IsExternal: yes; Reference: E-X1- Exterior
Name (Escalera moldeada in situ:Escalera:...) | In | NumberOfRiser | NumberOfTreads | RiserHeight (m) | TreadLength (m)
41321 | PS1- Gimnàs | 3 | 2 | 0.143333 | 0.3
41333 | PS1- Gimnàs | 7 | 6 | 0.142857 | 0.3
41677 | PS1- Gimnàs | 9 | 9 | 0.145556 | 0.301607
42180 | PS1- Vestuari | 9 | 8 | 0.145556 | 0.3
42246 | PS1- Vestuari | 7 | 8 | 0.16 | 0.3
42290 | PS1- Vestuari | 9 | 8 | 0.145556 | 0.3

# IfcStairFlight: Tramo monolítico:E00- STR- Acer (4)
In: PS1- Vestuari
Type - PredefinedType: STRAIGHT
TreadLength: 0.984252 m; Material: _PAV escales STR, _Acer- STR
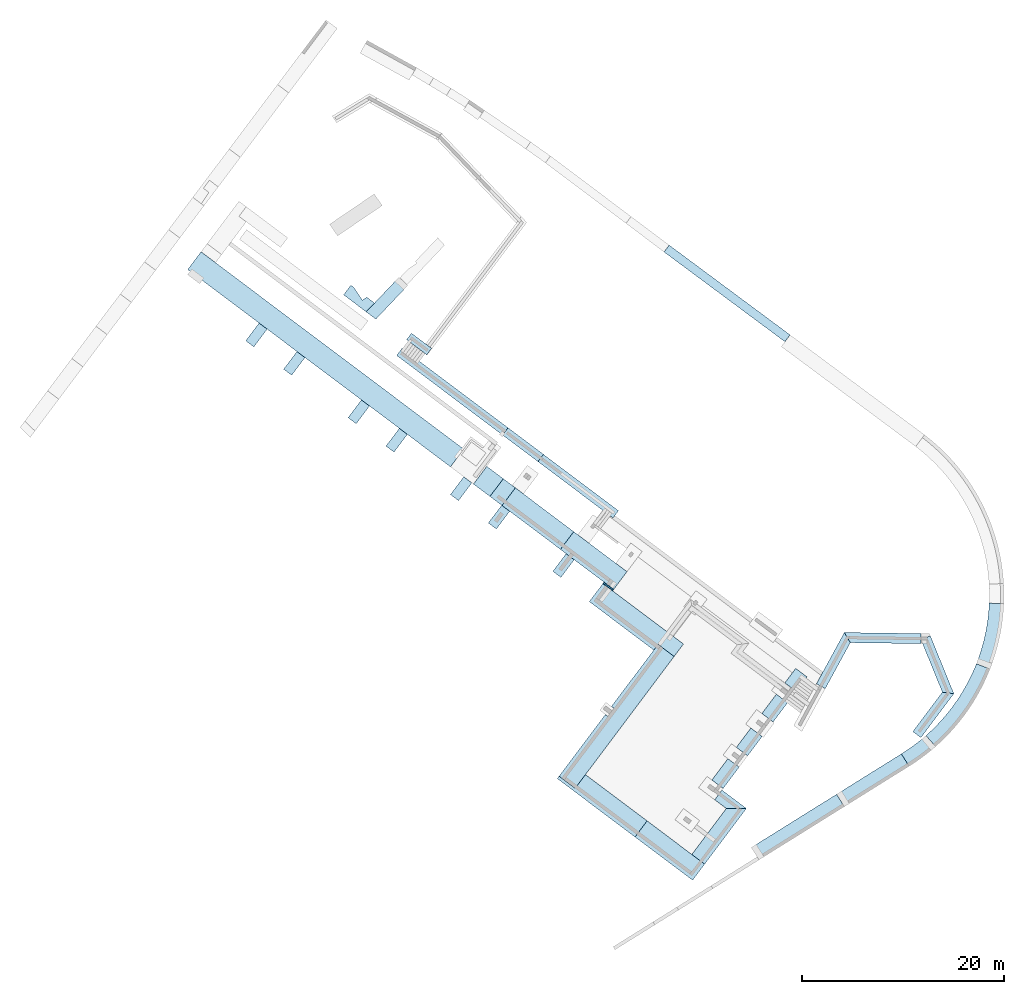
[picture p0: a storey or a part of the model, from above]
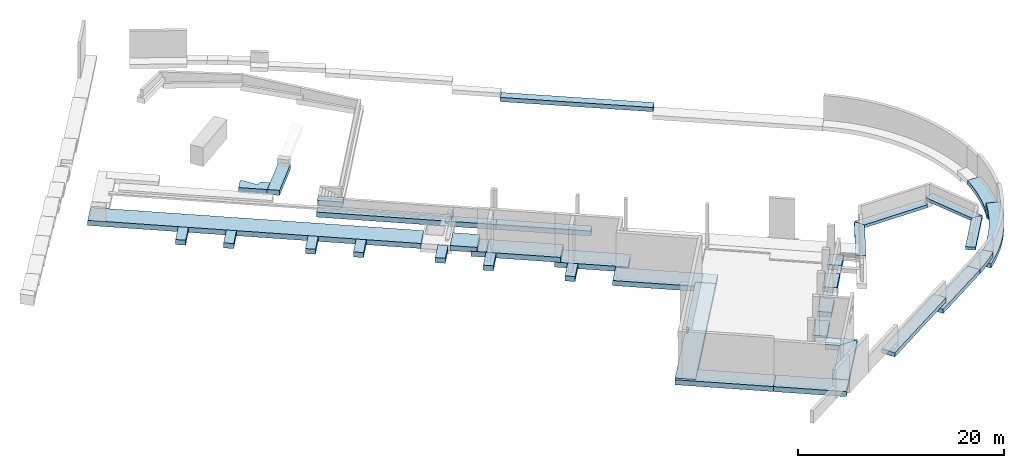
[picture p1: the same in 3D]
Properties of the parts of a building model (IFC2X3), part 3 of 3

# IfcStairFlight: Tramo monolítico:E00- STR- Acer (4)
Pset_QuantityTakeOff - Reference: E00- STR- Acer
Pset_StairFlightCommon - NosingLength: 0 m; Reference: E00- STR- Acer; TreadLength: 0.3 m; TreadLengthAtOffset: 0.3 m; TreadLengthAtInnerSide: 0.3 m
Name (Escalera moldeada in situ:Escalera:...) | NumberOfRiser = Pset_StairFlightCommon, NumberOfRiser | NumberOfTreads = Pset_StairFlightCommon, NumberOfTreads | RiserHeight (m) | Pset_StairFlightCommon, RiserHeight (m) | WalkingLineOffset (m)
43273 Run 1 | 4 | 4 | 0.524934 | 0.16 | 2.46063
43273 Run 2 | 12 | 11 | 0.524934 | 0.16 | 2.46063
43273 Run 3 | 12 | 12 | 0.524934 | 0.16 | 2.46063
92117 Run 1 | 10 | 10 | 0.577428 | 0.176 | 1.80446

# IfcStairFlight: Tramo monolítico:E00- STR- Ext, Escalera moldeada in situ:Escalera:41677 Run 1
In: PS1- Gimnàs
NumberOfRiser: 9; NumberOfTreads: 9; RiserHeight: 0.477544 m; TreadLength: 0.989525 m; Material: _Formigó- T1- STR
Pset_QuantityTakeOff - Reference: E00- STR- Ext
Pset_StairFlightCommon - Reference: E00- STR- Ext; NosingLength: 0 m; NumberOfRiser: 9; NumberOfTreads: 9; RiserHeight: 0.145556 m; TreadLength: 0.301607 m; TreadLengthAtOffset: 0.301607 m; TreadLengthAtInnerSide: 0.301607 m

# IfcStairFlight: Tramo monolítico:E00- STR- Ext (5)
Type - PredefinedType: STRAIGHT
TreadLength: 0.984252 m; Material: _Formigó- T1- STR
Pset_QuantityTakeOff - Reference: E00- STR- Ext
Pset_StairFlightCommon - Reference: E00- STR- Ext; TreadLength: 0.3 m; NosingLength: 0 m; TreadLengthAtOffset: 0.3 m; TreadLengthAtInnerSide: 0.3 m
Name (Escalera moldeada in situ:Escalera:...) | In | NumberOfRiser = Pset_StairFlightCommon, NumberOfRiser | NumberOfTreads = Pset_StairFlightCommon, NumberOfTreads | RiserHeight (m) | Pset_StairFlightCommon, RiserHeight (m) | WalkingLineOffset (m)
41321 Run 1 | PS1- Gimnàs | 3 | 2 | 0.470254 | 0.143333 | 3.1168
41333 Run 1 | PS1- Gimnàs | 7 | 6 | 0.468691 | 0.142857 | 2.46063
42180 Run 1 | PS1- Vestuari | 9 | 8 | 0.477544 | 0.145556 | 2.46063
42246 Run 1 | PS1- Vestuari | 7 | 8 | 0.524934 | 0.16 | 4.25689
42290 Run 1 | PS1- Vestuari | 9 | 8 | 0.477544 | 0.145556 | 2.46063

# IfcWall: Muro básico:STR- M- Formigó- Genèric- T1- 30 cm (8)
Type - PredefinedType: STANDARD; Material: _Formigó- T1- STR 0.3 m
Type - Pset_WallCommon - IsExternal: yes
Pset_QuantityTakeOff - Reference: STR- M- Formigó- Genèric- T1- 30 cm; sets with these values: 2
Pset_WallCommon - Reference: STR- M- Formigó- Genèric- T1- 30 cm; ExtendToStructure: no; LoadBearing: no
Name (Muro básico:STR- M- Formigó- Genèric- T1- 30 cm:...) | In
42194 | PS1- Gimnàs
42197 | PS1- Gimnàs
42200 | PS1- Gimnàs
42612 | P0- Escola | Group: Grupo de modelo:Mp-6 2:42619
42616 | P0- Escola | Group: Grupo de modelo:Mp-6 2:42619
42796 | P0- Escola | Group: Grupo de modelo:Mp-6 2:42619
113038 | P0- Escola | Group: Grupo de modelo:Murs urbanització 2:43208
154745 | PS1- Gimnàs

# IfcWallStandardCase: Muro básico:Muro 1, Muro básico:Muro 1:89267
In: PC- Coberta STR
Type - PredefinedType: STANDARD; Material: Muro por defecto 0.2 m
Type - Pset_WallCommon - IsExternal: yes
Pset_QuantityTakeOff - Reference: Muro 1; sets with these values: 2
Pset_WallCommon - ExtendToStructure: no; LoadBearing: no; Reference: Muro 1

# IfcWallStandardCase: Muro básico:STR- M- Bloc Formigó- T1- 15 cm (4)
Type - PredefinedType: STANDARD; Material: _Formigó- T1- STR 0.15 m
Type - Pset_WallCommon - IsExternal: yes
Pset_QuantityTakeOff - Reference: STR- M- Bloc Formigó- T1- 15 cm; sets with these values: 2
Pset_WallCommon - ExtendToStructure: no; LoadBearing: no; Reference: STR- M- Bloc Formigó- T1- 15 cm
Name (Muro básico:STR- M- Bloc Formigó- T1- 15 cm:...) | In
198168 | PS1- Vestuari
198231 | PS1- Vestuari
198289 | PS1- Vestuari
200422 | PC- Coberta STR

# IfcWallStandardCase: Muro básico:STR- M- Formigó- Genèric- T1- 20 cm (4)
Type - PredefinedType: STANDARD; Material: _Formigó- T1- STR 0.2 m
Type - Pset_WallCommon - IsExternal: yes
Pset_QuantityTakeOff - Reference: STR- M- Formigó- Genèric- T1- 20 cm; sets with these values: 2
Pset_WallCommon - ExtendToStructure: no; LoadBearing: no; Reference: STR- M- Formigó- Genèric- T1- 20 cm
Name (Muro básico:STR- M- Formigó- Genèric- T1- 20 cm:...) | In
42127 | PS1- Gimnàs | Group: Grupo de modelo:STR- conjunt soleres:41868
42228 | PS1- Vestuari
42229 | PS1- Vestuari
42230 | PS1- Vestuari

# IfcWallStandardCase: Muro básico:STR- M- Formigó- Genèric- T1- 25 cm (11)
In: P0- Escola
Type - PredefinedType: STANDARD; Material: _Formigó- T1- STR 0.25 m
Type - Pset_WallCommon - IsExternal: yes
Pset_QuantityTakeOff - Reference: STR- M- Formigó- Genèric- T1- 25 cm; sets with these values: 2
Pset_WallCommon - ExtendToStructure: no; Reference: STR- M- Formigó- Genèric- T1- 25 cm
Name (Muro básico:STR- M- Formigó- Genèric- T1- 25 cm:...) | LoadBearing
42025 | yes
42026 | yes
42027 | yes
42028 | yes
42029 | yes
42030 | yes
42031 | yes
42039 | yes
42041 | yes
43291 | no
88750 | yes

# IfcWallStandardCase: Muro básico:STR- M- Formigó- Genèric- T1- 30 cm (84)
Type - PredefinedType: STANDARD; Material: _Formigó- T1- STR 0.3 m
Type - Pset_WallCommon - IsExternal: yes
Pset_QuantityTakeOff - Reference: STR- M- Formigó- Genèric- T1- 30 cm; sets with these values: 2
Pset_WallCommon - Reference: STR- M- Formigó- Genèric- T1- 30 cm
Name (Muro básico:STR- M- Formigó- Genèric- T1- 30 cm:...) | In | LoadBearing | ExtendToStructure
41145 | P0- Escola | yes | no
41224 | PS1- Gimnàs | yes | no
41225 | PS1- Gimnàs | yes | yes
41226 | PS1- Gimnàs | yes | no
41332 | PS1- Vestuari | no | no
41483 | P0- Escola | no | no
41484 | P0- Escola | no | no
41502 | PS1- Vestuari | no | no
41644 | P0- Escola | no | no
41805 | P0- Escola | no | no
41806 | P0- Escola | no | no
41807 | P0- Escola | no | no
41808 | P0- Escola | no | no
41864 | PS1- Gimnàs | no | no
41865 | PS1- Gimnàs | no | no
41866 | PS1- Gimnàs | no | no
41867 | PS1- Gimnàs | no | no
41892 | PS1- Gimnàs | no | no
41989 | PS1- Gimnàs | no | no
42018 | PS1- Gimnàs | no | no
42024 | P0- Escola | no | no
42097 | PS1- Gimnàs | no | no
42156 | PS1- Gimnàs | no | yes
42177 | PS1- Gimnàs | no | yes
42191 | PS1- Gimnàs | no | no
42216 | PS1- Vestuari | no | no
42219 | PS1- Vestuari | no | no
42220 | PS1- Vestuari | no | no
42223 | PS1- Vestuari | no | no
42224 | PS1- Vestuari | no | no
42259 | PS1- Vestuari | no | no
42408 | PS1- Vestuari | no | no
42411 | PS1- Vestuari | no | no
42412 | P0- Escola | yes | no
42414 | PS1- Vestuari | no | no
42591 | PS1- Vestuari | no | no
42609 | P0- Escola | no | no | Group: Grupo de modelo:Mp-6 2:42619
42610 | P0- Escola | no | no | Group: Grupo de modelo:Mp-6 2:42619
42611 | P0- Escola | no | no | Group: Grupo de modelo:Mp-6 2:42619
42613 | P0- Escola | no | no | Group: Grupo de modelo:Mp-6 2:42619
42617 | P0- Escola | no | no | Group: Grupo de modelo:Mp-6 2:42619
42618 | P0- Escola | no | no | Group: Grupo de modelo:Mp-6 2:42619
42620 | P0- Escola | no | no | Group: Grupo de modelo:Mp-6 2:42619
42673 | P0- Escola | no | no | Group: Grupo de modelo:Mp-6 2:42619
42680 | P0- Escola | no | no | Group: Grupo de modelo:Mp-6 2:42619
42682 | P0- Escola | no | no
42821 | PS1- Vestuari | no | no | Group: Grupo de modelo:Mp-6 2:42619
42981 | P0- Escola | no | no | Group: Grupo de modelo:Murs urbanització 2:43208
43012 | PS1- Gimnàs | no | no | Group: Grupo de modelo:Murs urbanització 2:43208
43209 | PS1- Gimnàs | yes | no
43234 | PS1- Gimnàs | no | no
43235 | P0- Escola | no | no
43236 | P0- Escola | no | no
43271 | P0- Escola | no | no
112612 | P0- Escola | no | no
112613 | P0- Escola | no | no
112614 | P0- Escola | no | no
112615 | P0- Escola | no | no
112616 | P0- Escola | no | no
112617 | P0- Escola | no | no
112618 | P0- Escola | no | no
112619 | P0- Escola | no | no
112620 | P0- Escola | no | no
112621 | P0- Escola | no | no
112622 | P0- Escola | no | no
112623 | P0- Escola | no | no
112624 | P0- Escola | no | no
112625 | P0- Escola | no | no
112626 | P0- Escola | no | no
112627 | P0- Escola | no | no
112628 | P0- Escola | no | no
112629 | P0- Escola | no | no
112630 | P0- Escola | no | no
112631 | P0- Escola | no | no
113039 | P0- Escola | yes | no | Group: Grupo de modelo:Murs urbanització 2:43208
113041 | P0- Escola | no | no | Group: Grupo de modelo:Murs urbanització 2:43208
113042 | P0- Escola | no | no | Group: Grupo de modelo:Murs urbanització 2:43208
113044 | P0- Escola | no | no | Group: Grupo de modelo:Murs urbanització 2:43208
113045 | P0- Escola | no | no | Group: Grupo de modelo:Murs urbanització 2:43208
118791 | P0- Escola | no | no | Group: Grupo de modelo:Murs urbanització 2:43208
118928 | P0- Escola | no | no | Group: Grupo de modelo:Murs urbanització 2:43208
141595 | P0- Escola | no | no | Group: Grupo de modelo:Murs urbanització 2:43208
142522 | P0- Escola | no | no | Group: Grupo de modelo:Murs urbanització 2:43208
142714 | P0- Escola | no | no | Group: Grupo de modelo:Murs urbanització 2:43208

# IfcWallStandardCase: Muro básico:STR- M- Formigó- Genèric- T1- 35 cm (33)
Type - PredefinedType: STANDARD; Material: _Formigó- T1- STR 0.35 m
Type - Pset_WallCommon - IsExternal: yes
Pset_QuantityTakeOff - Reference: STR- M- Formigó- Genèric- T1- 35 cm; sets with these values: 2
Pset_WallCommon - Reference: STR- M- Formigó- Genèric- T1- 35 cm
Name (Muro básico:STR- M- Formigó- Genèric- T1- 35 cm:...) | In | LoadBearing | ExtendToStructure | Group
41223 | PS1- Gimnàs | yes | no
41313 | PS1- Gimnàs | yes | no
41425 | P0- Escola | no | no
41487 | PS1- Gimnàs | yes | no
41630 | PS1- Gimnàs | yes | yes
41877 | PS1- Gimnàs | yes | yes
42351 | PS1- Vestuari | no | no
42352 | PS1- Gimnàs | yes | no
42356 | PS1- Vestuari | no | no
42357 | PS1- Vestuari | no | no
42592 | PS1- Gimnàs | yes | no
43082 | PS1- Gimnàs | no | no | Grupo de modelo:Murs urbanització 2:43208
43083 | PS1- Gimnàs | no | no | Grupo de modelo:Murs urbanització 2:43208
43084 | PS1- Gimnàs | no | no | Grupo de modelo:Murs urbanització 2:43208
43085 | PS1- Vestuari | no | no | Grupo de modelo:Murs urbanització 2:43208
43086 | PS1- Vestuari | no | no | Grupo de modelo:Murs urbanització 2:43208
43093 | PS1- Gimnàs | no | no | Grupo de modelo:Murs urbanització 2:43208
43096 | PS1- Vestuari | no | no | Grupo de modelo:Murs urbanització 2:43208
43099 | PS1- Vestuari | no | no | Grupo de modelo:Murs urbanització 2:43208
43102 | PS1- Vestuari | no | no | Grupo de modelo:Murs urbanització 2:43208
43103 | PS1- Vestuari | no | no | Grupo de modelo:Murs urbanització 2:43208
43106 | PS1- Vestuari | no | no | Grupo de modelo:Murs urbanització 2:43208
43109 | PS1- Vestuari | no | no | Grupo de modelo:Murs urbanització 2:43208
43112 | PS1- Vestuari | no | no | Grupo de modelo:Murs urbanització 2:43208
43119 | PS1- Gimnàs | no | no | Grupo de modelo:Murs urbanització 2:43208
43122 | PS1- Gimnàs | no | no | Grupo de modelo:Murs urbanització 2:43208
43125 | PS1- Gimnàs | no | no | Grupo de modelo:Murs urbanització 2:43208
43126 | PS1- Gimnàs | no | no | Grupo de modelo:Murs urbanització 2:43208
43127 | PS1- Gimnàs | no | no | Grupo de modelo:Murs urbanització 2:43208
43132 | PS1- Gimnàs | no | no | Grupo de modelo:Murs urbanització 2:43208
43135 | PS1- Gimnàs | no | no | Grupo de modelo:Murs urbanització 2:43208
43138 | PS1- Gimnàs | no | no | Grupo de modelo:Murs urbanització 2:43208
43145 | PS1- Gimnàs | no | no | Grupo de modelo:Murs urbanització 2:43208

# IfcWallStandardCase: Muro básico:STR- M- Formigó- Genèric- T1- 40 cm (9)
Type - PredefinedType: STANDARD; Material: _Formigó- T1- STR 0.4 m
Type - Pset_WallCommon - IsExternal: yes
Pset_QuantityTakeOff - Reference: STR- M- Formigó- Genèric- T1- 40 cm; sets with these values: 2
Pset_WallCommon - Reference: STR- M- Formigó- Genèric- T1- 40 cm
Name (Muro básico:STR- M- Formigó- Genèric- T1- 40 cm:...) | In | LoadBearing | ExtendToStructure
41393 | PS1- Gimnàs | no | yes
41498 | PS1- Gimnàs | no | no
41499 | PS1- Vestuari | no | no
41500 | PS1- Gimnàs | yes | no
41774 | PS1- Vestuari | no | no
41780 | PS1- Vestuari | no | no
41786 | PS1- Vestuari | no | no
41792 | PS1- Vestuari | no | no
42019 | PS1- Gimnàs | no | no
